VERSION 5.8 ;
BUSBITCHARS "[]" ;
DIVIDERCHAR "/" ;
UNITS
    DATABASE MICRONS 1000 ;
END UNITS

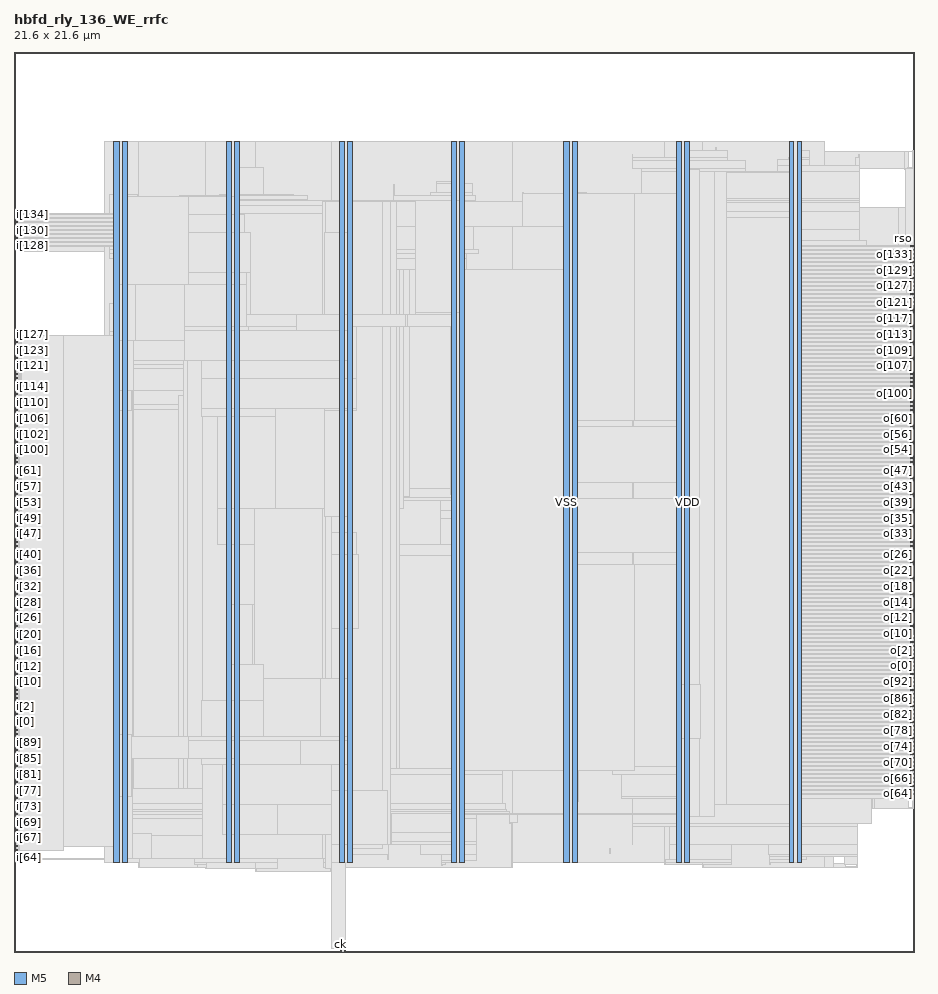
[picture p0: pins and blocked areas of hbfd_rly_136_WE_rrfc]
MACRO hbfd_rly_136_WE_rrfc
  FOREIGN hbfd_rly_136_WE_rrfc 0 0 ;
  CLASS BLOCK ;
  SIZE 21.6 BY 21.6 ;
  PIN ck
    DIRECTION INPUT ;
    USE SIGNAL ;
    PORT
      LAYER M5 ;
        RECT  7.824 0 7.848 0.084 ;
    END
  END ck
  PIN i[0]
    DIRECTION INPUT ;
    USE SIGNAL ;
    PORT
      LAYER M4 ;
        RECT  0 5.52 0.084 5.544 ;
    END
  END i[0]
  PIN i[100]
    DIRECTION INPUT ;
    USE SIGNAL ;
    PORT
      LAYER M4 ;
        RECT  0 12.048 0.084 12.072 ;
    END
  END i[100]
  PIN i[101]
    DIRECTION INPUT ;
    USE SIGNAL ;
    PORT
      LAYER M4 ;
        RECT  0 12.144 0.084 12.168 ;
    END
  END i[101]
  PIN i[102]
    DIRECTION INPUT ;
    USE SIGNAL ;
    PORT
      LAYER M4 ;
        RECT  0 12.24 0.084 12.264 ;
    END
  END i[102]
  PIN i[103]
    DIRECTION INPUT ;
    USE SIGNAL ;
    PORT
      LAYER M4 ;
        RECT  0 12.336 0.084 12.36 ;
    END
  END i[103]
  PIN i[104]
    DIRECTION INPUT ;
    USE SIGNAL ;
    PORT
      LAYER M4 ;
        RECT  0 12.432 0.084 12.456 ;
    END
  END i[104]
  PIN i[105]
    DIRECTION INPUT ;
    USE SIGNAL ;
    PORT
      LAYER M4 ;
        RECT  0 12.528 0.084 12.552 ;
    END
  END i[105]
  PIN i[106]
    DIRECTION INPUT ;
    USE SIGNAL ;
    PORT
      LAYER M4 ;
        RECT  0 12.624 0.084 12.648 ;
    END
  END i[106]
  PIN i[107]
    DIRECTION INPUT ;
    USE SIGNAL ;
    PORT
      LAYER M4 ;
        RECT  0 12.72 0.084 12.744 ;
    END
  END i[107]
  PIN i[108]
    DIRECTION INPUT ;
    USE SIGNAL ;
    PORT
      LAYER M4 ;
        RECT  0 12.816 0.084 12.84 ;
    END
  END i[108]
  PIN i[109]
    DIRECTION INPUT ;
    USE SIGNAL ;
    PORT
      LAYER M4 ;
        RECT  0 12.912 0.084 12.936 ;
    END
  END i[109]
  PIN i[10]
    DIRECTION INPUT ;
    USE SIGNAL ;
    PORT
      LAYER M4 ;
        RECT  0 6.48 0.084 6.504 ;
    END
  END i[10]
  PIN i[110]
    DIRECTION INPUT ;
    USE SIGNAL ;
    PORT
      LAYER M4 ;
        RECT  0 13.008 0.084 13.032 ;
    END
  END i[110]
  PIN i[111]
    DIRECTION INPUT ;
    USE SIGNAL ;
    PORT
      LAYER M4 ;
        RECT  0 13.104 0.084 13.128 ;
    END
  END i[111]
  PIN i[112]
    DIRECTION INPUT ;
    USE SIGNAL ;
    PORT
      LAYER M4 ;
        RECT  0 13.2 0.084 13.224 ;
    END
  END i[112]
  PIN i[113]
    DIRECTION INPUT ;
    USE SIGNAL ;
    PORT
      LAYER M4 ;
        RECT  0 13.296 0.084 13.32 ;
    END
  END i[113]
  PIN i[114]
    DIRECTION INPUT ;
    USE SIGNAL ;
    PORT
      LAYER M4 ;
        RECT  0 13.392 0.084 13.416 ;
    END
  END i[114]
  PIN i[115]
    DIRECTION INPUT ;
    USE SIGNAL ;
    PORT
      LAYER M4 ;
        RECT  0 13.488 0.084 13.512 ;
    END
  END i[115]
  PIN i[116]
    DIRECTION INPUT ;
    USE SIGNAL ;
    PORT
      LAYER M4 ;
        RECT  0 13.584 0.084 13.608 ;
    END
  END i[116]
  PIN i[117]
    DIRECTION INPUT ;
    USE SIGNAL ;
    PORT
      LAYER M4 ;
        RECT  0 13.68 0.084 13.704 ;
    END
  END i[117]
  PIN i[118]
    DIRECTION INPUT ;
    USE SIGNAL ;
    PORT
      LAYER M4 ;
        RECT  0 13.776 0.084 13.8 ;
    END
  END i[118]
  PIN i[119]
    DIRECTION INPUT ;
    USE SIGNAL ;
    PORT
      LAYER M4 ;
        RECT  0 13.872 0.084 13.896 ;
    END
  END i[119]
  PIN i[11]
    DIRECTION INPUT ;
    USE SIGNAL ;
    PORT
      LAYER M4 ;
        RECT  0 6.576 0.084 6.6 ;
    END
  END i[11]
  PIN i[120]
    DIRECTION INPUT ;
    USE SIGNAL ;
    PORT
      LAYER M4 ;
        RECT  0 13.968 0.084 13.992 ;
    END
  END i[120]
  PIN i[121]
    DIRECTION INPUT ;
    USE SIGNAL ;
    PORT
      LAYER M4 ;
        RECT  0 14.064 0.084 14.088 ;
    END
  END i[121]
  PIN i[122]
    DIRECTION INPUT ;
    USE SIGNAL ;
    PORT
      LAYER M4 ;
        RECT  0 14.16 0.084 14.184 ;
    END
  END i[122]
  PIN i[123]
    DIRECTION INPUT ;
    USE SIGNAL ;
    PORT
      LAYER M4 ;
        RECT  0 14.256 0.084 14.28 ;
    END
  END i[123]
  PIN i[124]
    DIRECTION INPUT ;
    USE SIGNAL ;
    PORT
      LAYER M4 ;
        RECT  0 14.352 0.084 14.376 ;
    END
  END i[124]
  PIN i[125]
    DIRECTION INPUT ;
    USE SIGNAL ;
    PORT
      LAYER M4 ;
        RECT  0 14.448 0.084 14.472 ;
    END
  END i[125]
  PIN i[126]
    DIRECTION INPUT ;
    USE SIGNAL ;
    PORT
      LAYER M4 ;
        RECT  0 14.544 0.084 14.568 ;
    END
  END i[126]
  PIN i[127]
    DIRECTION INPUT ;
    USE SIGNAL ;
    PORT
      LAYER M4 ;
        RECT  0 14.64 0.084 14.664 ;
    END
  END i[127]
  PIN i[128]
    DIRECTION INPUT ;
    USE SIGNAL ;
    PORT
      LAYER M4 ;
        RECT  0 16.944 0.084 16.968 ;
    END
  END i[128]
  PIN i[129]
    DIRECTION INPUT ;
    USE SIGNAL ;
    PORT
      LAYER M4 ;
        RECT  0 17.04 0.084 17.064 ;
    END
  END i[129]
  PIN i[12]
    DIRECTION INPUT ;
    USE SIGNAL ;
    PORT
      LAYER M4 ;
        RECT  0 6.672 0.084 6.696 ;
    END
  END i[12]
  PIN i[130]
    DIRECTION INPUT ;
    USE SIGNAL ;
    PORT
      LAYER M4 ;
        RECT  0 17.136 0.084 17.16 ;
    END
  END i[130]
  PIN i[131]
    DIRECTION INPUT ;
    USE SIGNAL ;
    PORT
      LAYER M4 ;
        RECT  0 17.232 0.084 17.256 ;
    END
  END i[131]
  PIN i[132]
    DIRECTION INPUT ;
    USE SIGNAL ;
    PORT
      LAYER M4 ;
        RECT  0 17.328 0.084 17.352 ;
    END
  END i[132]
  PIN i[133]
    DIRECTION INPUT ;
    USE SIGNAL ;
    PORT
      LAYER M4 ;
        RECT  0 17.424 0.084 17.448 ;
    END
  END i[133]
  PIN i[134]
    DIRECTION INPUT ;
    USE SIGNAL ;
    PORT
      LAYER M4 ;
        RECT  0 17.52 0.084 17.544 ;
    END
  END i[134]
  PIN i[135]
    DIRECTION INPUT ;
    USE SIGNAL ;
    PORT
      LAYER M4 ;
        RECT  0 17.616 0.084 17.64 ;
    END
  END i[135]
  PIN i[13]
    DIRECTION INPUT ;
    USE SIGNAL ;
    PORT
      LAYER M4 ;
        RECT  0 6.768 0.084 6.792 ;
    END
  END i[13]
  PIN i[14]
    DIRECTION INPUT ;
    USE SIGNAL ;
    PORT
      LAYER M4 ;
        RECT  0 6.864 0.084 6.888 ;
    END
  END i[14]
  PIN i[15]
    DIRECTION INPUT ;
    USE SIGNAL ;
    PORT
      LAYER M4 ;
        RECT  0 6.96 0.084 6.984 ;
    END
  END i[15]
  PIN i[16]
    DIRECTION INPUT ;
    USE SIGNAL ;
    PORT
      LAYER M4 ;
        RECT  0 7.056 0.084 7.08 ;
    END
  END i[16]
  PIN i[17]
    DIRECTION INPUT ;
    USE SIGNAL ;
    PORT
      LAYER M4 ;
        RECT  0 7.152 0.084 7.176 ;
    END
  END i[17]
  PIN i[18]
    DIRECTION INPUT ;
    USE SIGNAL ;
    PORT
      LAYER M4 ;
        RECT  0 7.248 0.084 7.272 ;
    END
  END i[18]
  PIN i[19]
    DIRECTION INPUT ;
    USE SIGNAL ;
    PORT
      LAYER M4 ;
        RECT  0 7.344 0.084 7.368 ;
    END
  END i[19]
  PIN i[1]
    DIRECTION INPUT ;
    USE SIGNAL ;
    PORT
      LAYER M4 ;
        RECT  0 5.616 0.084 5.64 ;
    END
  END i[1]
  PIN i[20]
    DIRECTION INPUT ;
    USE SIGNAL ;
    PORT
      LAYER M4 ;
        RECT  0 7.44 0.084 7.464 ;
    END
  END i[20]
  PIN i[21]
    DIRECTION INPUT ;
    USE SIGNAL ;
    PORT
      LAYER M4 ;
        RECT  0 7.536 0.084 7.56 ;
    END
  END i[21]
  PIN i[22]
    DIRECTION INPUT ;
    USE SIGNAL ;
    PORT
      LAYER M4 ;
        RECT  0 7.632 0.084 7.656 ;
    END
  END i[22]
  PIN i[23]
    DIRECTION INPUT ;
    USE SIGNAL ;
    PORT
      LAYER M4 ;
        RECT  0 7.728 0.084 7.752 ;
    END
  END i[23]
  PIN i[24]
    DIRECTION INPUT ;
    USE SIGNAL ;
    PORT
      LAYER M4 ;
        RECT  0 7.824 0.084 7.848 ;
    END
  END i[24]
  PIN i[25]
    DIRECTION INPUT ;
    USE SIGNAL ;
    PORT
      LAYER M4 ;
        RECT  0 7.92 0.084 7.944 ;
    END
  END i[25]
  PIN i[26]
    DIRECTION INPUT ;
    USE SIGNAL ;
    PORT
      LAYER M4 ;
        RECT  0 8.016 0.084 8.04 ;
    END
  END i[26]
  PIN i[27]
    DIRECTION INPUT ;
    USE SIGNAL ;
    PORT
      LAYER M4 ;
        RECT  0 8.112 0.084 8.136 ;
    END
  END i[27]
  PIN i[28]
    DIRECTION INPUT ;
    USE SIGNAL ;
    PORT
      LAYER M4 ;
        RECT  0 8.208 0.084 8.232 ;
    END
  END i[28]
  PIN i[29]
    DIRECTION INPUT ;
    USE SIGNAL ;
    PORT
      LAYER M4 ;
        RECT  0 8.304 0.084 8.328 ;
    END
  END i[29]
  PIN i[2]
    DIRECTION INPUT ;
    USE SIGNAL ;
    PORT
      LAYER M4 ;
        RECT  0 5.712 0.084 5.736 ;
    END
  END i[2]
  PIN i[30]
    DIRECTION INPUT ;
    USE SIGNAL ;
    PORT
      LAYER M4 ;
        RECT  0 8.4 0.084 8.424 ;
    END
  END i[30]
  PIN i[31]
    DIRECTION INPUT ;
    USE SIGNAL ;
    PORT
      LAYER M4 ;
        RECT  0 8.496 0.084 8.52 ;
    END
  END i[31]
  PIN i[32]
    DIRECTION INPUT ;
    USE SIGNAL ;
    PORT
      LAYER M4 ;
        RECT  0 8.592 0.084 8.616 ;
    END
  END i[32]
  PIN i[33]
    DIRECTION INPUT ;
    USE SIGNAL ;
    PORT
      LAYER M4 ;
        RECT  0 8.688 0.084 8.712 ;
    END
  END i[33]
  PIN i[34]
    DIRECTION INPUT ;
    USE SIGNAL ;
    PORT
      LAYER M4 ;
        RECT  0 8.784 0.084 8.808 ;
    END
  END i[34]
  PIN i[35]
    DIRECTION INPUT ;
    USE SIGNAL ;
    PORT
      LAYER M4 ;
        RECT  0 8.88 0.084 8.904 ;
    END
  END i[35]
  PIN i[36]
    DIRECTION INPUT ;
    USE SIGNAL ;
    PORT
      LAYER M4 ;
        RECT  0 8.976 0.084 9 ;
    END
  END i[36]
  PIN i[37]
    DIRECTION INPUT ;
    USE SIGNAL ;
    PORT
      LAYER M4 ;
        RECT  0 9.072 0.084 9.096 ;
    END
  END i[37]
  PIN i[38]
    DIRECTION INPUT ;
    USE SIGNAL ;
    PORT
      LAYER M4 ;
        RECT  0 9.168 0.084 9.192 ;
    END
  END i[38]
  PIN i[39]
    DIRECTION INPUT ;
    USE SIGNAL ;
    PORT
      LAYER M4 ;
        RECT  0 9.264 0.084 9.288 ;
    END
  END i[39]
  PIN i[3]
    DIRECTION INPUT ;
    USE SIGNAL ;
    PORT
      LAYER M4 ;
        RECT  0 5.808 0.084 5.832 ;
    END
  END i[3]
  PIN i[40]
    DIRECTION INPUT ;
    USE SIGNAL ;
    PORT
      LAYER M4 ;
        RECT  0 9.36 0.084 9.384 ;
    END
  END i[40]
  PIN i[41]
    DIRECTION INPUT ;
    USE SIGNAL ;
    PORT
      LAYER M4 ;
        RECT  0 9.456 0.084 9.48 ;
    END
  END i[41]
  PIN i[42]
    DIRECTION INPUT ;
    USE SIGNAL ;
    PORT
      LAYER M4 ;
        RECT  0 9.552 0.084 9.576 ;
    END
  END i[42]
  PIN i[43]
    DIRECTION INPUT ;
    USE SIGNAL ;
    PORT
      LAYER M4 ;
        RECT  0 9.648 0.084 9.672 ;
    END
  END i[43]
  PIN i[44]
    DIRECTION INPUT ;
    USE SIGNAL ;
    PORT
      LAYER M4 ;
        RECT  0 9.744 0.084 9.768 ;
    END
  END i[44]
  PIN i[45]
    DIRECTION INPUT ;
    USE SIGNAL ;
    PORT
      LAYER M4 ;
        RECT  0 9.84 0.084 9.864 ;
    END
  END i[45]
  PIN i[46]
    DIRECTION INPUT ;
    USE SIGNAL ;
    PORT
      LAYER M4 ;
        RECT  0 9.936 0.084 9.96 ;
    END
  END i[46]
  PIN i[47]
    DIRECTION INPUT ;
    USE SIGNAL ;
    PORT
      LAYER M4 ;
        RECT  0 10.032 0.084 10.056 ;
    END
  END i[47]
  PIN i[48]
    DIRECTION INPUT ;
    USE SIGNAL ;
    PORT
      LAYER M4 ;
        RECT  0 10.128 0.084 10.152 ;
    END
  END i[48]
  PIN i[49]
    DIRECTION INPUT ;
    USE SIGNAL ;
    PORT
      LAYER M4 ;
        RECT  0 10.224 0.084 10.248 ;
    END
  END i[49]
  PIN i[4]
    DIRECTION INPUT ;
    USE SIGNAL ;
    PORT
      LAYER M4 ;
        RECT  0 5.904 0.084 5.928 ;
    END
  END i[4]
  PIN i[50]
    DIRECTION INPUT ;
    USE SIGNAL ;
    PORT
      LAYER M4 ;
        RECT  0 10.32 0.084 10.344 ;
    END
  END i[50]
  PIN i[51]
    DIRECTION INPUT ;
    USE SIGNAL ;
    PORT
      LAYER M4 ;
        RECT  0 10.416 0.084 10.44 ;
    END
  END i[51]
  PIN i[52]
    DIRECTION INPUT ;
    USE SIGNAL ;
    PORT
      LAYER M4 ;
        RECT  0 10.512 0.084 10.536 ;
    END
  END i[52]
  PIN i[53]
    DIRECTION INPUT ;
    USE SIGNAL ;
    PORT
      LAYER M4 ;
        RECT  0 10.608 0.084 10.632 ;
    END
  END i[53]
  PIN i[54]
    DIRECTION INPUT ;
    USE SIGNAL ;
    PORT
      LAYER M4 ;
        RECT  0 10.704 0.084 10.728 ;
    END
  END i[54]
  PIN i[55]
    DIRECTION INPUT ;
    USE SIGNAL ;
    PORT
      LAYER M4 ;
        RECT  0 10.8 0.084 10.824 ;
    END
  END i[55]
  PIN i[56]
    DIRECTION INPUT ;
    USE SIGNAL ;
    PORT
      LAYER M4 ;
        RECT  0 10.896 0.084 10.92 ;
    END
  END i[56]
  PIN i[57]
    DIRECTION INPUT ;
    USE SIGNAL ;
    PORT
      LAYER M4 ;
        RECT  0 10.992 0.084 11.016 ;
    END
  END i[57]
  PIN i[58]
    DIRECTION INPUT ;
    USE SIGNAL ;
    PORT
      LAYER M4 ;
        RECT  0 11.088 0.084 11.112 ;
    END
  END i[58]
  PIN i[59]
    DIRECTION INPUT ;
    USE SIGNAL ;
    PORT
      LAYER M4 ;
        RECT  0 11.184 0.084 11.208 ;
    END
  END i[59]
  PIN i[5]
    DIRECTION INPUT ;
    USE SIGNAL ;
    PORT
      LAYER M4 ;
        RECT  0 6 0.084 6.024 ;
    END
  END i[5]
  PIN i[60]
    DIRECTION INPUT ;
    USE SIGNAL ;
    PORT
      LAYER M4 ;
        RECT  0 11.28 0.084 11.304 ;
    END
  END i[60]
  PIN i[61]
    DIRECTION INPUT ;
    USE SIGNAL ;
    PORT
      LAYER M4 ;
        RECT  0 11.376 0.084 11.4 ;
    END
  END i[61]
  PIN i[62]
    DIRECTION INPUT ;
    USE SIGNAL ;
    PORT
      LAYER M4 ;
        RECT  0 11.472 0.084 11.496 ;
    END
  END i[62]
  PIN i[63]
    DIRECTION INPUT ;
    USE SIGNAL ;
    PORT
      LAYER M4 ;
        RECT  0 11.568 0.084 11.592 ;
    END
  END i[63]
  PIN i[64]
    DIRECTION INPUT ;
    USE SIGNAL ;
    PORT
      LAYER M4 ;
        RECT  0 2.448 0.084 2.472 ;
    END
  END i[64]
  PIN i[65]
    DIRECTION INPUT ;
    USE SIGNAL ;
    PORT
      LAYER M4 ;
        RECT  0 2.544 0.084 2.568 ;
    END
  END i[65]
  PIN i[66]
    DIRECTION INPUT ;
    USE SIGNAL ;
    PORT
      LAYER M4 ;
        RECT  0 2.64 0.084 2.664 ;
    END
  END i[66]
  PIN i[67]
    DIRECTION INPUT ;
    USE SIGNAL ;
    PORT
      LAYER M4 ;
        RECT  0 2.736 0.084 2.76 ;
    END
  END i[67]
  PIN i[68]
    DIRECTION INPUT ;
    USE SIGNAL ;
    PORT
      LAYER M4 ;
        RECT  0 2.832 0.084 2.856 ;
    END
  END i[68]
  PIN i[69]
    DIRECTION INPUT ;
    USE SIGNAL ;
    PORT
      LAYER M4 ;
        RECT  0 2.928 0.084 2.952 ;
    END
  END i[69]
  PIN i[6]
    DIRECTION INPUT ;
    USE SIGNAL ;
    PORT
      LAYER M4 ;
        RECT  0 6.096 0.084 6.12 ;
    END
  END i[6]
  PIN i[70]
    DIRECTION INPUT ;
    USE SIGNAL ;
    PORT
      LAYER M4 ;
        RECT  0 3.024 0.084 3.048 ;
    END
  END i[70]
  PIN i[71]
    DIRECTION INPUT ;
    USE SIGNAL ;
    PORT
      LAYER M4 ;
        RECT  0 3.12 0.084 3.144 ;
    END
  END i[71]
  PIN i[72]
    DIRECTION INPUT ;
    USE SIGNAL ;
    PORT
      LAYER M4 ;
        RECT  0 3.216 0.084 3.24 ;
    END
  END i[72]
  PIN i[73]
    DIRECTION INPUT ;
    USE SIGNAL ;
    PORT
      LAYER M4 ;
        RECT  0 3.312 0.084 3.336 ;
    END
  END i[73]
  PIN i[74]
    DIRECTION INPUT ;
    USE SIGNAL ;
    PORT
      LAYER M4 ;
        RECT  0 3.408 0.084 3.432 ;
    END
  END i[74]
  PIN i[75]
    DIRECTION INPUT ;
    USE SIGNAL ;
    PORT
      LAYER M4 ;
        RECT  0 3.504 0.084 3.528 ;
    END
  END i[75]
  PIN i[76]
    DIRECTION INPUT ;
    USE SIGNAL ;
    PORT
      LAYER M4 ;
        RECT  0 3.6 0.084 3.624 ;
    END
  END i[76]
  PIN i[77]
    DIRECTION INPUT ;
    USE SIGNAL ;
    PORT
      LAYER M4 ;
        RECT  0 3.696 0.084 3.72 ;
    END
  END i[77]
  PIN i[78]
    DIRECTION INPUT ;
    USE SIGNAL ;
    PORT
      LAYER M4 ;
        RECT  0 3.792 0.084 3.816 ;
    END
  END i[78]
  PIN i[79]
    DIRECTION INPUT ;
    USE SIGNAL ;
    PORT
      LAYER M4 ;
        RECT  0 3.888 0.084 3.912 ;
    END
  END i[79]
  PIN i[7]
    DIRECTION INPUT ;
    USE SIGNAL ;
    PORT
      LAYER M4 ;
        RECT  0 6.192 0.084 6.216 ;
    END
  END i[7]
  PIN i[80]
    DIRECTION INPUT ;
    USE SIGNAL ;
    PORT
      LAYER M4 ;
        RECT  0 3.984 0.084 4.008 ;
    END
  END i[80]
  PIN i[81]
    DIRECTION INPUT ;
    USE SIGNAL ;
    PORT
      LAYER M4 ;
        RECT  0 4.08 0.084 4.104 ;
    END
  END i[81]
  PIN i[82]
    DIRECTION INPUT ;
    USE SIGNAL ;
    PORT
      LAYER M4 ;
        RECT  0 4.176 0.084 4.2 ;
    END
  END i[82]
  PIN i[83]
    DIRECTION INPUT ;
    USE SIGNAL ;
    PORT
      LAYER M4 ;
        RECT  0 4.272 0.084 4.296 ;
    END
  END i[83]
  PIN i[84]
    DIRECTION INPUT ;
    USE SIGNAL ;
    PORT
      LAYER M4 ;
        RECT  0 4.368 0.084 4.392 ;
    END
  END i[84]
  PIN i[85]
    DIRECTION INPUT ;
    USE SIGNAL ;
    PORT
      LAYER M4 ;
        RECT  0 4.464 0.084 4.488 ;
    END
  END i[85]
  PIN i[86]
    DIRECTION INPUT ;
    USE SIGNAL ;
    PORT
      LAYER M4 ;
        RECT  0 4.56 0.084 4.584 ;
    END
  END i[86]
  PIN i[87]
    DIRECTION INPUT ;
    USE SIGNAL ;
    PORT
      LAYER M4 ;
        RECT  0 4.656 0.084 4.68 ;
    END
  END i[87]
  PIN i[88]
    DIRECTION INPUT ;
    USE SIGNAL ;
    PORT
      LAYER M4 ;
        RECT  0 4.752 0.084 4.776 ;
    END
  END i[88]
  PIN i[89]
    DIRECTION INPUT ;
    USE SIGNAL ;
    PORT
      LAYER M4 ;
        RECT  0 4.848 0.084 4.872 ;
    END
  END i[89]
  PIN i[8]
    DIRECTION INPUT ;
    USE SIGNAL ;
    PORT
      LAYER M4 ;
        RECT  0 6.288 0.084 6.312 ;
    END
  END i[8]
  PIN i[90]
    DIRECTION INPUT ;
    USE SIGNAL ;
    PORT
      LAYER M4 ;
        RECT  0 4.944 0.084 4.968 ;
    END
  END i[90]
  PIN i[91]
    DIRECTION INPUT ;
    USE SIGNAL ;
    PORT
      LAYER M4 ;
        RECT  0 5.04 0.084 5.064 ;
    END
  END i[91]
  PIN i[92]
    DIRECTION INPUT ;
    USE SIGNAL ;
    PORT
      LAYER M4 ;
        RECT  0 5.136 0.084 5.16 ;
    END
  END i[92]
  PIN i[93]
    DIRECTION INPUT ;
    USE SIGNAL ;
    PORT
      LAYER M4 ;
        RECT  0 5.232 0.084 5.256 ;
    END
  END i[93]
  PIN i[94]
    DIRECTION INPUT ;
    USE SIGNAL ;
    PORT
      LAYER M4 ;
        RECT  0 5.328 0.084 5.352 ;
    END
  END i[94]
  PIN i[95]
    DIRECTION INPUT ;
    USE SIGNAL ;
    PORT
      LAYER M4 ;
        RECT  0 5.424 0.084 5.448 ;
    END
  END i[95]
  PIN i[96]
    DIRECTION INPUT ;
    USE SIGNAL ;
    PORT
      LAYER M4 ;
        RECT  0 11.664 0.084 11.688 ;
    END
  END i[96]
  PIN i[97]
    DIRECTION INPUT ;
    USE SIGNAL ;
    PORT
      LAYER M4 ;
        RECT  0 11.76 0.084 11.784 ;
    END
  END i[97]
  PIN i[98]
    DIRECTION INPUT ;
    USE SIGNAL ;
    PORT
      LAYER M4 ;
        RECT  0 11.856 0.084 11.88 ;
    END
  END i[98]
  PIN i[99]
    DIRECTION INPUT ;
    USE SIGNAL ;
    PORT
      LAYER M4 ;
        RECT  0 11.952 0.084 11.976 ;
    END
  END i[99]
  PIN i[9]
    DIRECTION INPUT ;
    USE SIGNAL ;
    PORT
      LAYER M4 ;
        RECT  0 6.384 0.084 6.408 ;
    END
  END i[9]
  PIN o[0]
    DIRECTION OUTPUT ;
    USE SIGNAL ;
    PORT
      LAYER M4 ;
        RECT  21.516 6.864 21.6 6.888 ;
    END
  END o[0]
  PIN o[100]
    DIRECTION OUTPUT ;
    USE SIGNAL ;
    PORT
      LAYER M4 ;
        RECT  21.516 13.392 21.6 13.416 ;
    END
  END o[100]
  PIN o[101]
    DIRECTION OUTPUT ;
    USE SIGNAL ;
    PORT
      LAYER M4 ;
        RECT  21.516 13.488 21.6 13.512 ;
    END
  END o[101]
  PIN o[102]
    DIRECTION OUTPUT ;
    USE SIGNAL ;
    PORT
      LAYER M4 ;
        RECT  21.516 13.584 21.6 13.608 ;
    END
  END o[102]
  PIN o[103]
    DIRECTION OUTPUT ;
    USE SIGNAL ;
    PORT
      LAYER M4 ;
        RECT  21.516 13.68 21.6 13.704 ;
    END
  END o[103]
  PIN o[104]
    DIRECTION OUTPUT ;
    USE SIGNAL ;
    PORT
      LAYER M4 ;
        RECT  21.516 13.776 21.6 13.8 ;
    END
  END o[104]
  PIN o[105]
    DIRECTION OUTPUT ;
    USE SIGNAL ;
    PORT
      LAYER M4 ;
        RECT  21.516 13.872 21.6 13.896 ;
    END
  END o[105]
  PIN o[106]
    DIRECTION OUTPUT ;
    USE SIGNAL ;
    PORT
      LAYER M4 ;
        RECT  21.516 13.968 21.6 13.992 ;
    END
  END o[106]
  PIN o[107]
    DIRECTION OUTPUT ;
    USE SIGNAL ;
    PORT
      LAYER M4 ;
        RECT  21.516 14.064 21.6 14.088 ;
    END
  END o[107]
  PIN o[108]
    DIRECTION OUTPUT ;
    USE SIGNAL ;
    PORT
      LAYER M4 ;
        RECT  21.516 14.16 21.6 14.184 ;
    END
  END o[108]
  PIN o[109]
    DIRECTION OUTPUT ;
    USE SIGNAL ;
    PORT
      LAYER M4 ;
        RECT  21.516 14.256 21.6 14.28 ;
    END
  END o[109]
  PIN o[10]
    DIRECTION OUTPUT ;
    USE SIGNAL ;
    PORT
      LAYER M4 ;
        RECT  21.516 7.824 21.6 7.848 ;
    END
  END o[10]
  PIN o[110]
    DIRECTION OUTPUT ;
    USE SIGNAL ;
    PORT
      LAYER M4 ;
        RECT  21.516 14.352 21.6 14.376 ;
    END
  END o[110]
  PIN o[111]
    DIRECTION OUTPUT ;
    USE SIGNAL ;
    PORT
      LAYER M4 ;
        RECT  21.516 14.448 21.6 14.472 ;
    END
  END o[111]
  PIN o[112]
    DIRECTION OUTPUT ;
    USE SIGNAL ;
    PORT
      LAYER M4 ;
        RECT  21.516 14.544 21.6 14.568 ;
    END
  END o[112]
  PIN o[113]
    DIRECTION OUTPUT ;
    USE SIGNAL ;
    PORT
      LAYER M4 ;
        RECT  21.516 14.64 21.6 14.664 ;
    END
  END o[113]
  PIN o[114]
    DIRECTION OUTPUT ;
    USE SIGNAL ;
    PORT
      LAYER M4 ;
        RECT  21.516 14.736 21.6 14.76 ;
    END
  END o[114]
  PIN o[115]
    DIRECTION OUTPUT ;
    USE SIGNAL ;
    PORT
      LAYER M4 ;
        RECT  21.516 14.832 21.6 14.856 ;
    END
  END o[115]
  PIN o[116]
    DIRECTION OUTPUT ;
    USE SIGNAL ;
    PORT
      LAYER M4 ;
        RECT  21.516 14.928 21.6 14.952 ;
    END
  END o[116]
  PIN o[117]
    DIRECTION OUTPUT ;
    USE SIGNAL ;
    PORT
      LAYER M4 ;
        RECT  21.516 15.024 21.6 15.048 ;
    END
  END o[117]
  PIN o[118]
    DIRECTION OUTPUT ;
    USE SIGNAL ;
    PORT
      LAYER M4 ;
        RECT  21.516 15.12 21.6 15.144 ;
    END
  END o[118]
  PIN o[119]
    DIRECTION OUTPUT ;
    USE SIGNAL ;
    PORT
      LAYER M4 ;
        RECT  21.516 15.216 21.6 15.24 ;
    END
  END o[119]
  PIN o[11]
    DIRECTION OUTPUT ;
    USE SIGNAL ;
    PORT
      LAYER M4 ;
        RECT  21.516 7.92 21.6 7.944 ;
    END
  END o[11]
  PIN o[120]
    DIRECTION OUTPUT ;
    USE SIGNAL ;
    PORT
      LAYER M4 ;
        RECT  21.516 15.312 21.6 15.336 ;
    END
  END o[120]
  PIN o[121]
    DIRECTION OUTPUT ;
    USE SIGNAL ;
    PORT
      LAYER M4 ;
        RECT  21.516 15.408 21.6 15.432 ;
    END
  END o[121]
  PIN o[122]
    DIRECTION OUTPUT ;
    USE SIGNAL ;
    PORT
      LAYER M4 ;
        RECT  21.516 15.504 21.6 15.528 ;
    END
  END o[122]
  PIN o[123]
    DIRECTION OUTPUT ;
    USE SIGNAL ;
    PORT
      LAYER M4 ;
        RECT  21.516 15.6 21.6 15.624 ;
    END
  END o[123]
  PIN o[124]
    DIRECTION OUTPUT ;
    USE SIGNAL ;
    PORT
      LAYER M4 ;
        RECT  21.516 15.696 21.6 15.72 ;
    END
  END o[124]
  PIN o[125]
    DIRECTION OUTPUT ;
    USE SIGNAL ;
    PORT
      LAYER M4 ;
        RECT  21.516 15.792 21.6 15.816 ;
    END
  END o[125]
  PIN o[126]
    DIRECTION OUTPUT ;
    USE SIGNAL ;
    PORT
      LAYER M4 ;
        RECT  21.516 15.888 21.6 15.912 ;
    END
  END o[126]
  PIN o[127]
    DIRECTION OUTPUT ;
    USE SIGNAL ;
    PORT
      LAYER M4 ;
        RECT  21.516 15.984 21.6 16.008 ;
    END
  END o[127]
  PIN o[128]
    DIRECTION OUTPUT ;
    USE SIGNAL ;
    PORT
      LAYER M4 ;
        RECT  21.516 16.08 21.6 16.104 ;
    END
  END o[128]
  PIN o[129]
    DIRECTION OUTPUT ;
    USE SIGNAL ;
    PORT
      LAYER M4 ;
        RECT  21.516 16.176 21.6 16.2 ;
    END
  END o[129]
  PIN o[12]
    DIRECTION OUTPUT ;
    USE SIGNAL ;
    PORT
      LAYER M4 ;
        RECT  21.516 8.016 21.6 8.04 ;
    END
  END o[12]
  PIN o[130]
    DIRECTION OUTPUT ;
    USE SIGNAL ;
    PORT
      LAYER M4 ;
        RECT  21.516 16.272 21.6 16.296 ;
    END
  END o[130]
  PIN o[131]
    DIRECTION OUTPUT ;
    USE SIGNAL ;
    PORT
      LAYER M4 ;
        RECT  21.516 16.368 21.6 16.392 ;
    END
  END o[131]
  PIN o[132]
    DIRECTION OUTPUT ;
    USE SIGNAL ;
    PORT
      LAYER M4 ;
        RECT  21.516 16.464 21.6 16.488 ;
    END
  END o[132]
  PIN o[133]
    DIRECTION OUTPUT ;
    USE SIGNAL ;
    PORT
      LAYER M4 ;
        RECT  21.516 16.56 21.6 16.584 ;
    END
  END o[133]
  PIN o[134]
    DIRECTION OUTPUT ;
    USE SIGNAL ;
    PORT
      LAYER M4 ;
        RECT  21.516 16.656 21.6 16.68 ;
    END
  END o[134]
  PIN o[135]
    DIRECTION OUTPUT ;
    USE SIGNAL ;
    PORT
      LAYER M4 ;
        RECT  21.516 16.752 21.6 16.776 ;
    END
  END o[135]
  PIN o[13]
    DIRECTION OUTPUT ;
    USE SIGNAL ;
    PORT
      LAYER M4 ;
        RECT  21.516 8.112 21.6 8.136 ;
    END
  END o[13]
  PIN o[14]
    DIRECTION OUTPUT ;
    USE SIGNAL ;
    PORT
      LAYER M4 ;
        RECT  21.516 8.208 21.6 8.232 ;
    END
  END o[14]
  PIN o[15]
    DIRECTION OUTPUT ;
    USE SIGNAL ;
    PORT
      LAYER M4 ;
        RECT  21.516 8.304 21.6 8.328 ;
    END
  END o[15]
  PIN o[16]
    DIRECTION OUTPUT ;
    USE SIGNAL ;
    PORT
      LAYER M4 ;
        RECT  21.516 8.4 21.6 8.424 ;
    END
  END o[16]
  PIN o[17]
    DIRECTION OUTPUT ;
    USE SIGNAL ;
    PORT
      LAYER M4 ;
        RECT  21.516 8.496 21.6 8.52 ;
    END
  END o[17]
  PIN o[18]
    DIRECTION OUTPUT ;
    USE SIGNAL ;
    PORT
      LAYER M4 ;
        RECT  21.516 8.592 21.6 8.616 ;
    END
  END o[18]
  PIN o[19]
    DIRECTION OUTPUT ;
    USE SIGNAL ;
    PORT
      LAYER M4 ;
        RECT  21.516 8.688 21.6 8.712 ;
    END
  END o[19]
  PIN o[1]
    DIRECTION OUTPUT ;
    USE SIGNAL ;
    PORT
      LAYER M4 ;
        RECT  21.516 6.96 21.6 6.984 ;
    END
  END o[1]
  PIN o[20]
    DIRECTION OUTPUT ;
    USE SIGNAL ;
    PORT
      LAYER M4 ;
        RECT  21.516 8.784 21.6 8.808 ;
    END
  END o[20]
  PIN o[21]
    DIRECTION OUTPUT ;
    USE SIGNAL ;
    PORT
      LAYER M4 ;
        RECT  21.516 8.88 21.6 8.904 ;
    END
  END o[21]
  PIN o[22]
    DIRECTION OUTPUT ;
    USE SIGNAL ;
    PORT
      LAYER M4 ;
        RECT  21.516 8.976 21.6 9 ;
    END
  END o[22]
  PIN o[23]
    DIRECTION OUTPUT ;
    USE SIGNAL ;
    PORT
      LAYER M4 ;
        RECT  21.516 9.072 21.6 9.096 ;
    END
  END o[23]
  PIN o[24]
    DIRECTION OUTPUT ;
    USE SIGNAL ;
    PORT
      LAYER M4 ;
        RECT  21.516 9.168 21.6 9.192 ;
    END
  END o[24]
  PIN o[25]
    DIRECTION OUTPUT ;
    USE SIGNAL ;
    PORT
      LAYER M4 ;
        RECT  21.516 9.264 21.6 9.288 ;
    END
  END o[25]
  PIN o[26]
    DIRECTION OUTPUT ;
    USE SIGNAL ;
    PORT
      LAYER M4 ;
        RECT  21.516 9.36 21.6 9.384 ;
    END
  END o[26]
  PIN o[27]
    DIRECTION OUTPUT ;
    USE SIGNAL ;
    PORT
      LAYER M4 ;
        RECT  21.516 9.456 21.6 9.48 ;
    END
  END o[27]
  PIN o[28]
    DIRECTION OUTPUT ;
    USE SIGNAL ;
    PORT
      LAYER M4 ;
        RECT  21.516 9.552 21.6 9.576 ;
    END
  END o[28]
  PIN o[29]
    DIRECTION OUTPUT ;
    USE SIGNAL ;
    PORT
      LAYER M4 ;
        RECT  21.516 9.648 21.6 9.672 ;
    END
  END o[29]
  PIN o[2]
    DIRECTION OUTPUT ;
    USE SIGNAL ;
    PORT
      LAYER M4 ;
        RECT  21.516 7.056 21.6 7.08 ;
    END
  END o[2]
  PIN o[30]
    DIRECTION OUTPUT ;
    USE SIGNAL ;
    PORT
      LAYER M4 ;
        RECT  21.516 9.744 21.6 9.768 ;
    END
  END o[30]
  PIN o[31]
    DIRECTION OUTPUT ;
    USE SIGNAL ;
    PORT
      LAYER M4 ;
        RECT  21.516 9.84 21.6 9.864 ;
    END
  END o[31]
  PIN o[32]
    DIRECTION OUTPUT ;
    USE SIGNAL ;
    PORT
      LAYER M4 ;
        RECT  21.516 9.936 21.6 9.96 ;
    END
  END o[32]
  PIN o[33]
    DIRECTION OUTPUT ;
    USE SIGNAL ;
    PORT
      LAYER M4 ;
        RECT  21.516 10.032 21.6 10.056 ;
    END
  END o[33]
  PIN o[34]
    DIRECTION OUTPUT ;
    USE SIGNAL ;
    PORT
      LAYER M4 ;
        RECT  21.516 10.128 21.6 10.152 ;
    END
  END o[34]
  PIN o[35]
    DIRECTION OUTPUT ;
    USE SIGNAL ;
    PORT
      LAYER M4 ;
        RECT  21.516 10.224 21.6 10.248 ;
    END
  END o[35]
  PIN o[36]
    DIRECTION OUTPUT ;
    USE SIGNAL ;
    PORT
      LAYER M4 ;
        RECT  21.516 10.32 21.6 10.344 ;
    END
  END o[36]
  PIN o[37]
    DIRECTION OUTPUT ;
    USE SIGNAL ;
    PORT
      LAYER M4 ;
        RECT  21.516 10.416 21.6 10.44 ;
    END
  END o[37]
  PIN o[38]
    DIRECTION OUTPUT ;
    USE SIGNAL ;
    PORT
      LAYER M4 ;
        RECT  21.516 10.512 21.6 10.536 ;
    END
  END o[38]
  PIN o[39]
    DIRECTION OUTPUT ;
    USE SIGNAL ;
    PORT
      LAYER M4 ;
        RECT  21.516 10.608 21.6 10.632 ;
    END
  END o[39]
  PIN o[3]
    DIRECTION OUTPUT ;
    USE SIGNAL ;
    PORT
      LAYER M4 ;
        RECT  21.516 7.152 21.6 7.176 ;
    END
  END o[3]
  PIN o[40]
    DIRECTION OUTPUT ;
    USE SIGNAL ;
    PORT
      LAYER M4 ;
        RECT  21.516 10.704 21.6 10.728 ;
    END
  END o[40]
  PIN o[41]
    DIRECTION OUTPUT ;
    USE SIGNAL ;
    PORT
      LAYER M4 ;
        RECT  21.516 10.8 21.6 10.824 ;
    END
  END o[41]
  PIN o[42]
    DIRECTION OUTPUT ;
    USE SIGNAL ;
    PORT
      LAYER M4 ;
        RECT  21.516 10.896 21.6 10.92 ;
    END
  END o[42]
  PIN o[43]
    DIRECTION OUTPUT ;
    USE SIGNAL ;
    PORT
      LAYER M4 ;
        RECT  21.516 10.992 21.6 11.016 ;
    END
  END o[43]
  PIN o[44]
    DIRECTION OUTPUT ;
    USE SIGNAL ;
    PORT
      LAYER M4 ;
        RECT  21.516 11.088 21.6 11.112 ;
    END
  END o[44]
  PIN o[45]
    DIRECTION OUTPUT ;
    USE SIGNAL ;
    PORT
      LAYER M4 ;
        RECT  21.516 11.184 21.6 11.208 ;
    END
  END o[45]
  PIN o[46]
    DIRECTION OUTPUT ;
    USE SIGNAL ;
    PORT
      LAYER M4 ;
        RECT  21.516 11.28 21.6 11.304 ;
    END
  END o[46]
  PIN o[47]
    DIRECTION OUTPUT ;
    USE SIGNAL ;
    PORT
      LAYER M4 ;
        RECT  21.516 11.376 21.6 11.4 ;
    END
  END o[47]
  PIN o[48]
    DIRECTION OUTPUT ;
    USE SIGNAL ;
    PORT
      LAYER M4 ;
        RECT  21.516 11.472 21.6 11.496 ;
    END
  END o[48]
  PIN o[49]
    DIRECTION OUTPUT ;
    USE SIGNAL ;
    PORT
      LAYER M4 ;
        RECT  21.516 11.568 21.6 11.592 ;
    END
  END o[49]
  PIN o[4]
    DIRECTION OUTPUT ;
    USE SIGNAL ;
    PORT
      LAYER M4 ;
        RECT  21.516 7.248 21.6 7.272 ;
    END
  END o[4]
  PIN o[50]
    DIRECTION OUTPUT ;
    USE SIGNAL ;
    PORT
      LAYER M4 ;
        RECT  21.516 11.664 21.6 11.688 ;
    END
  END o[50]
  PIN o[51]
    DIRECTION OUTPUT ;
    USE SIGNAL ;
    PORT
      LAYER M4 ;
        RECT  21.516 11.76 21.6 11.784 ;
    END
  END o[51]
  PIN o[52]
    DIRECTION OUTPUT ;
    USE SIGNAL ;
    PORT
      LAYER M4 ;
        RECT  21.516 11.856 21.6 11.88 ;
    END
  END o[52]
  PIN o[53]
    DIRECTION OUTPUT ;
    USE SIGNAL ;
    PORT
      LAYER M4 ;
        RECT  21.516 11.952 21.6 11.976 ;
    END
  END o[53]
  PIN o[54]
    DIRECTION OUTPUT ;
    USE SIGNAL ;
    PORT
      LAYER M4 ;
        RECT  21.516 12.048 21.6 12.072 ;
    END
  END o[54]
  PIN o[55]
    DIRECTION OUTPUT ;
    USE SIGNAL ;
    PORT
      LAYER M4 ;
        RECT  21.516 12.144 21.6 12.168 ;
    END
  END o[55]
  PIN o[56]
    DIRECTION OUTPUT ;
    USE SIGNAL ;
    PORT
      LAYER M4 ;
        RECT  21.516 12.24 21.6 12.264 ;
    END
  END o[56]
  PIN o[57]
    DIRECTION OUTPUT ;
    USE SIGNAL ;
    PORT
      LAYER M4 ;
        RECT  21.516 12.336 21.6 12.36 ;
    END
  END o[57]
  PIN o[58]
    DIRECTION OUTPUT ;
    USE SIGNAL ;
    PORT
      LAYER M4 ;
        RECT  21.516 12.432 21.6 12.456 ;
    END
  END o[58]
  PIN o[59]
    DIRECTION OUTPUT ;
    USE SIGNAL ;
    PORT
      LAYER M4 ;
        RECT  21.516 12.528 21.6 12.552 ;
    END
  END o[59]
  PIN o[5]
    DIRECTION OUTPUT ;
    USE SIGNAL ;
    PORT
      LAYER M4 ;
        RECT  21.516 7.344 21.6 7.368 ;
    END
  END o[5]
  PIN o[60]
    DIRECTION OUTPUT ;
    USE SIGNAL ;
    PORT
      LAYER M4 ;
        RECT  21.516 12.624 21.6 12.648 ;
    END
  END o[60]
  PIN o[61]
    DIRECTION OUTPUT ;
    USE SIGNAL ;
    PORT
      LAYER M4 ;
        RECT  21.516 12.72 21.6 12.744 ;
    END
  END o[61]
  PIN o[62]
    DIRECTION OUTPUT ;
    USE SIGNAL ;
    PORT
      LAYER M4 ;
        RECT  21.516 12.816 21.6 12.84 ;
    END
  END o[62]
  PIN o[63]
    DIRECTION OUTPUT ;
    USE SIGNAL ;
    PORT
      LAYER M4 ;
        RECT  21.516 12.912 21.6 12.936 ;
    END
  END o[63]
  PIN o[64]
    DIRECTION OUTPUT ;
    USE SIGNAL ;
    PORT
      LAYER M4 ;
        RECT  21.516 3.792 21.6 3.816 ;
    END
  END o[64]
  PIN o[65]
    DIRECTION OUTPUT ;
    USE SIGNAL ;
    PORT
      LAYER M4 ;
        RECT  21.516 3.888 21.6 3.912 ;
    END
  END o[65]
  PIN o[66]
    DIRECTION OUTPUT ;
    USE SIGNAL ;
    PORT
      LAYER M4 ;
        RECT  21.516 3.984 21.6 4.008 ;
    END
  END o[66]
  PIN o[67]
    DIRECTION OUTPUT ;
    USE SIGNAL ;
    PORT
      LAYER M4 ;
        RECT  21.516 4.08 21.6 4.104 ;
    END
  END o[67]
  PIN o[68]
    DIRECTION OUTPUT ;
    USE SIGNAL ;
    PORT
      LAYER M4 ;
        RECT  21.516 4.176 21.6 4.2 ;
    END
  END o[68]
  PIN o[69]
    DIRECTION OUTPUT ;
    USE SIGNAL ;
    PORT
      LAYER M4 ;
        RECT  21.516 4.272 21.6 4.296 ;
    END
  END o[69]
  PIN o[6]
    DIRECTION OUTPUT ;
    USE SIGNAL ;
    PORT
      LAYER M4 ;
        RECT  21.516 7.44 21.6 7.464 ;
    END
  END o[6]
  PIN o[70]
    DIRECTION OUTPUT ;
    USE SIGNAL ;
    PORT
      LAYER M4 ;
        RECT  21.516 4.368 21.6 4.392 ;
    END
  END o[70]
  PIN o[71]
    DIRECTION OUTPUT ;
    USE SIGNAL ;
    PORT
      LAYER M4 ;
        RECT  21.516 4.464 21.6 4.488 ;
    END
  END o[71]
  PIN o[72]
    DIRECTION OUTPUT ;
    USE SIGNAL ;
    PORT
      LAYER M4 ;
        RECT  21.516 4.56 21.6 4.584 ;
    END
  END o[72]
  PIN o[73]
    DIRECTION OUTPUT ;
    USE SIGNAL ;
    PORT
      LAYER M4 ;
        RECT  21.516 4.656 21.6 4.68 ;
    END
  END o[73]
  PIN o[74]
    DIRECTION OUTPUT ;
    USE SIGNAL ;
    PORT
      LAYER M4 ;
        RECT  21.516 4.752 21.6 4.776 ;
    END
  END o[74]
  PIN o[75]
    DIRECTION OUTPUT ;
    USE SIGNAL ;
    PORT
      LAYER M4 ;
        RECT  21.516 4.848 21.6 4.872 ;
    END
  END o[75]
  PIN o[76]
    DIRECTION OUTPUT ;
    USE SIGNAL ;
    PORT
      LAYER M4 ;
        RECT  21.516 4.944 21.6 4.968 ;
    END
  END o[76]
  PIN o[77]
    DIRECTION OUTPUT ;
    USE SIGNAL ;
    PORT
      LAYER M4 ;
        RECT  21.516 5.04 21.6 5.064 ;
    END
  END o[77]
  PIN o[78]
    DIRECTION OUTPUT ;
    USE SIGNAL ;
    PORT
      LAYER M4 ;
        RECT  21.516 5.136 21.6 5.16 ;
    END
  END o[78]
  PIN o[79]
    DIRECTION OUTPUT ;
    USE SIGNAL ;
    PORT
      LAYER M4 ;
        RECT  21.516 5.232 21.6 5.256 ;
    END
  END o[79]
  PIN o[7]
    DIRECTION OUTPUT ;
    USE SIGNAL ;
    PORT
      LAYER M4 ;
        RECT  21.516 7.536 21.6 7.56 ;
    END
  END o[7]
  PIN o[80]
    DIRECTION OUTPUT ;
    USE SIGNAL ;
    PORT
      LAYER M4 ;
        RECT  21.516 5.328 21.6 5.352 ;
    END
  END o[80]
  PIN o[81]
    DIRECTION OUTPUT ;
    USE SIGNAL ;
    PORT
      LAYER M4 ;
        RECT  21.516 5.424 21.6 5.448 ;
    END
  END o[81]
  PIN o[82]
    DIRECTION OUTPUT ;
    USE SIGNAL ;
    PORT
      LAYER M4 ;
        RECT  21.516 5.52 21.6 5.544 ;
    END
  END o[82]
  PIN o[83]
    DIRECTION OUTPUT ;
    USE SIGNAL ;
    PORT
      LAYER M4 ;
        RECT  21.516 5.616 21.6 5.64 ;
    END
  END o[83]
  PIN o[84]
    DIRECTION OUTPUT ;
    USE SIGNAL ;
    PORT
      LAYER M4 ;
        RECT  21.516 5.712 21.6 5.736 ;
    END
  END o[84]
  PIN o[85]
    DIRECTION OUTPUT ;
    USE SIGNAL ;
    PORT
      LAYER M4 ;
        RECT  21.516 5.808 21.6 5.832 ;
    END
  END o[85]
  PIN o[86]
    DIRECTION OUTPUT ;
    USE SIGNAL ;
    PORT
      LAYER M4 ;
        RECT  21.516 5.904 21.6 5.928 ;
    END
  END o[86]
  PIN o[87]
    DIRECTION OUTPUT ;
    USE SIGNAL ;
    PORT
      LAYER M4 ;
        RECT  21.516 6 21.6 6.024 ;
    END
  END o[87]
  PIN o[88]
    DIRECTION OUTPUT ;
    USE SIGNAL ;
    PORT
      LAYER M4 ;
        RECT  21.516 6.096 21.6 6.12 ;
    END
  END o[88]
  PIN o[89]
    DIRECTION OUTPUT ;
    USE SIGNAL ;
    PORT
      LAYER M4 ;
        RECT  21.516 6.192 21.6 6.216 ;
    END
  END o[89]
  PIN o[8]
    DIRECTION OUTPUT ;
    USE SIGNAL ;
    PORT
      LAYER M4 ;
        RECT  21.516 7.632 21.6 7.656 ;
    END
  END o[8]
  PIN o[90]
    DIRECTION OUTPUT ;
    USE SIGNAL ;
    PORT
      LAYER M4 ;
        RECT  21.516 6.288 21.6 6.312 ;
    END
  END o[90]
  PIN o[91]
    DIRECTION OUTPUT ;
    USE SIGNAL ;
    PORT
      LAYER M4 ;
        RECT  21.516 6.384 21.6 6.408 ;
    END
  END o[91]
  PIN o[92]
    DIRECTION OUTPUT ;
    USE SIGNAL ;
    PORT
      LAYER M4 ;
        RECT  21.516 6.48 21.6 6.504 ;
    END
  END o[92]
  PIN o[93]
    DIRECTION OUTPUT ;
    USE SIGNAL ;
    PORT
      LAYER M4 ;
        RECT  21.516 6.576 21.6 6.6 ;
    END
  END o[93]
  PIN o[94]
    DIRECTION OUTPUT ;
    USE SIGNAL ;
    PORT
      LAYER M4 ;
        RECT  21.516 6.672 21.6 6.696 ;
    END
  END o[94]
  PIN o[95]
    DIRECTION OUTPUT ;
    USE SIGNAL ;
    PORT
      LAYER M4 ;
        RECT  21.516 6.768 21.6 6.792 ;
    END
  END o[95]
  PIN o[96]
    DIRECTION OUTPUT ;
    USE SIGNAL ;
    PORT
      LAYER M4 ;
        RECT  21.516 13.008 21.6 13.032 ;
    END
  END o[96]
  PIN o[97]
    DIRECTION OUTPUT ;
    USE SIGNAL ;
    PORT
      LAYER M4 ;
        RECT  21.516 13.104 21.6 13.128 ;
    END
  END o[97]
  PIN o[98]
    DIRECTION OUTPUT ;
    USE SIGNAL ;
    PORT
      LAYER M4 ;
        RECT  21.516 13.2 21.6 13.224 ;
    END
  END o[98]
  PIN o[99]
    DIRECTION OUTPUT ;
    USE SIGNAL ;
    PORT
      LAYER M4 ;
        RECT  21.516 13.296 21.6 13.32 ;
    END
  END o[99]
  PIN o[9]
    DIRECTION OUTPUT ;
    USE SIGNAL ;
    PORT
      LAYER M4 ;
        RECT  21.516 7.728 21.6 7.752 ;
    END
  END o[9]
  PIN rfi
    DIRECTION INPUT ;
    USE SIGNAL ;
    PORT
      LAYER M4 ;
        RECT  0 17.712 0.084 17.736 ;
    END
  END rfi
  PIN rfo
    DIRECTION OUTPUT ;
    USE SIGNAL ;
    PORT
      LAYER M4 ;
        RECT  21.516 16.848 21.6 16.872 ;
    END
  END rfo
  PIN rs
    DIRECTION INPUT ;
    USE SIGNAL ;
    PORT
      LAYER M5 ;
        RECT  7.92 0 7.944 0.084 ;
    END
  END rs
  PIN rso
    DIRECTION OUTPUT ;
    USE SIGNAL ;
    PORT
      LAYER M4 ;
        RECT  21.516 16.944 21.6 16.968 ;
    END
  END rso
  PIN VDD
    DIRECTION INOUT ;
    USE POWER ;
    PORT
      LAYER M5 ;
        RECT  18.792 2.151 18.912 19.449 ;
        RECT  16.092 2.151 16.212 19.449 ;
        RECT  13.392 2.151 13.512 19.449 ;
        RECT  10.692 2.151 10.812 19.449 ;
        RECT  7.992 2.151 8.112 19.449 ;
        RECT  5.292 2.151 5.412 19.449 ;
        RECT  2.592 2.151 2.712 19.449 ;
    END
  END VDD
  PIN VSS
    DIRECTION INOUT ;
    USE GROUND ;
    PORT
      LAYER M5 ;
        RECT  18.6 2.137 18.72 19.463 ;
        RECT  15.9 2.137 16.02 19.463 ;
        RECT  13.2 2.137 13.32 19.463 ;
        RECT  10.5 2.137 10.62 19.463 ;
        RECT  7.8 2.137 7.92 19.463 ;
        RECT  5.1 2.137 5.22 19.463 ;
        RECT  2.4 2.137 2.52 19.463 ;
    END
  END VSS
  # OT_OBS_CLOSED layer=M5 d_um=1.536 added=26
  OBS
    LAYER RVTN ;
     RECT  2.16 2.16 19.44 2.295 ;
     RECT  2.16 2.565 19.44 2.835 ;
     RECT  2.16 3.105 19.44 3.375 ;
     RECT  2.16 3.645 19.44 3.915 ;
     RECT  2.16 4.185 19.44 4.455 ;
     RECT  2.16 4.725 19.44 4.995 ;
     RECT  2.16 5.265 19.44 5.535 ;
     RECT  2.16 5.805 19.44 6.075 ;
     RECT  2.16 6.345 19.44 6.615 ;
     RECT  2.16 6.885 19.44 7.155 ;
     RECT  2.16 7.425 19.44 7.695 ;
     RECT  2.16 7.965 19.44 8.235 ;
     RECT  2.16 8.505 19.44 8.775 ;
     RECT  2.16 9.045 19.44 9.315 ;
     RECT  2.16 9.585 19.44 9.855 ;
     RECT  2.16 10.125 19.44 10.395 ;
     RECT  2.16 10.665 19.44 10.935 ;
     RECT  2.16 11.205 19.44 11.475 ;
     RECT  2.16 11.745 19.44 12.015 ;
     RECT  2.16 12.285 19.44 12.555 ;
     RECT  2.16 12.825 19.44 13.095 ;
     RECT  2.16 13.365 19.44 13.635 ;
     RECT  2.16 13.905 19.44 14.175 ;
     RECT  2.16 14.445 19.44 14.715 ;
     RECT  2.16 14.985 19.44 15.255 ;
     RECT  2.16 15.525 19.44 15.795 ;
     RECT  2.16 16.065 19.44 16.335 ;
     RECT  2.16 16.605 19.44 16.875 ;
     RECT  2.16 17.145 19.44 17.415 ;
     RECT  2.16 17.685 19.44 17.955 ;
     RECT  2.16 18.225 19.44 18.495 ;
     RECT  2.16 18.765 19.44 19.035 ;
     RECT  2.16 19.305 19.44 19.44 ;
    LAYER RVTP ;
     RECT  2.16 2.295 19.44 2.565 ;
     RECT  2.16 2.835 19.44 3.105 ;
     RECT  2.16 3.375 19.44 3.645 ;
     RECT  2.16 3.915 19.44 4.185 ;
     RECT  2.16 4.455 19.44 4.725 ;
     RECT  2.16 4.995 19.44 5.265 ;
     RECT  2.16 5.535 19.44 5.805 ;
     RECT  2.16 6.075 19.44 6.345 ;
     RECT  2.16 6.615 19.44 6.885 ;
     RECT  2.16 7.155 19.44 7.425 ;
     RECT  2.16 7.695 19.44 7.965 ;
     RECT  2.16 8.235 19.44 8.505 ;
     RECT  2.16 8.775 19.44 9.045 ;
     RECT  2.16 9.315 19.44 9.585 ;
     RECT  2.16 9.855 19.44 10.125 ;
     RECT  2.16 10.395 19.44 10.665 ;
     RECT  2.16 10.935 19.44 11.205 ;
     RECT  2.16 11.475 19.44 11.745 ;
     RECT  2.16 12.015 19.44 12.285 ;
     RECT  2.16 12.555 19.44 12.825 ;
     RECT  2.16 13.095 19.44 13.365 ;
     RECT  2.16 13.635 19.44 13.905 ;
     RECT  2.16 14.175 19.44 14.445 ;
     RECT  2.16 14.715 19.44 14.985 ;
     RECT  2.16 15.255 19.44 15.525 ;
     RECT  2.16 15.795 19.44 16.065 ;
     RECT  2.16 16.335 19.44 16.605 ;
     RECT  2.16 16.875 19.44 17.145 ;
     RECT  2.16 17.415 19.44 17.685 ;
     RECT  2.16 17.955 19.44 18.225 ;
     RECT  2.16 18.495 19.44 18.765 ;
     RECT  2.16 19.035 19.44 19.305 ;
    LAYER M1 ;
     RECT  2.16 2.151 19.44 19.449 ;
    LAYER M2 ;
     RECT  0.103 17.082 0.139 17.1 ;
     RECT  0.103 5.85 0.175 5.868 ;
     RECT  0.103 6.66 0.175 6.678 ;
     RECT  0.103 7.938 0.463 7.956 ;
     RECT  0.175 5.85 0.499 6.678 ;
     RECT  0.463 7.776 0.499 7.956 ;
     RECT  0.103 5.004 0.535 5.022 ;
     RECT  0.499 5.85 0.535 7.956 ;
     RECT  0.499 9.054 0.535 9.072 ;
     RECT  0.103 11.79 0.535 11.808 ;
     RECT  0.535 5.004 1.147 5.058 ;
     RECT  0.103 3.69 1.975 3.708 ;
     RECT  1.147 4.662 1.975 5.058 ;
     RECT  0.535 5.85 1.975 9.072 ;
     RECT  1.147 10.404 2.155 10.422 ;
     RECT  0.535 11.79 2.155 12.348 ;
     RECT  0.103 2.232 2.16 2.25 ;
     RECT  1.975 3.69 2.16 5.058 ;
     RECT  1.975 5.85 2.16 9.378 ;
     RECT  2.155 10.404 2.16 10.926 ;
     RECT  2.155 11.79 2.16 12.618 ;
     RECT  0.139 16.812 2.16 17.1 ;
     RECT  2.16 2.151 2.983 19.449 ;
     RECT  2.983 2.034 4.603 19.449 ;
     RECT  4.603 1.998 5.791 19.449 ;
     RECT  5.791 1.926 7.619 19.449 ;
     RECT  7.619 2.034 11.975 19.449 ;
     RECT  11.975 2.151 15.619 19.449 ;
     RECT  15.619 2.106 16.519 19.449 ;
     RECT  16.519 2.034 19.44 19.449 ;
     RECT  19.44 2.034 19.679 8.334 ;
     RECT  19.44 9.09 19.931 12.384 ;
     RECT  19.44 13.176 19.931 15.354 ;
     RECT  19.679 2.034 19.967 2.124 ;
     RECT  19.679 2.916 20.219 8.334 ;
     RECT  19.931 9.09 20.219 11.034 ;
     RECT  19.967 2.034 20.255 2.052 ;
     RECT  20.219 9.09 20.435 9.882 ;
     RECT  20.435 9.216 20.471 9.882 ;
     RECT  20.219 3.078 20.507 8.334 ;
     RECT  20.219 10.836 20.507 11.034 ;
     RECT  20.507 5.346 20.543 8.334 ;
     RECT  20.507 11.016 20.543 11.034 ;
     RECT  19.931 11.826 20.543 12.384 ;
     RECT  19.931 13.176 20.543 15.282 ;
     RECT  20.507 3.078 20.579 4.518 ;
     RECT  20.543 5.346 20.579 5.724 ;
     RECT  20.543 6.588 20.579 8.334 ;
     RECT  20.579 3.456 20.615 4.518 ;
     RECT  20.579 8.316 20.615 8.334 ;
     RECT  20.615 3.456 20.651 3.978 ;
     RECT  20.543 14.526 21.235 15.282 ;
     RECT  19.44 16.146 21.235 17.874 ;
     RECT  20.579 6.588 21.343 7.488 ;
     RECT  19.44 18.81 21.379 19.224 ;
     RECT  21.235 14.526 21.407 17.874 ;
     RECT  20.579 5.346 21.415 5.364 ;
     RECT  20.471 9.324 21.415 9.882 ;
     RECT  20.543 11.826 21.415 12.348 ;
     RECT  21.407 16.578 21.443 17.874 ;
     RECT  20.651 3.456 21.479 3.87 ;
     RECT  20.543 13.608 21.479 13.626 ;
     RECT  21.407 14.526 21.479 15.786 ;
     RECT  21.443 17.46 21.479 17.874 ;
     RECT  21.379 18.774 21.479 19.224 ;
     RECT  21.415 5.346 21.515 5.634 ;
     RECT  21.343 6.588 21.515 7.65 ;
     RECT  21.415 8.856 21.515 9.882 ;
     RECT  21.415 11.556 21.515 12.744 ;
     RECT  21.479 14.526 21.515 14.544 ;
     RECT  21.479 17.856 21.515 17.874 ;
     RECT  21.479 3.456 21.587 3.474 ;
     RECT  21.515 7.632 21.587 7.65 ;
     RECT  21.479 15.534 21.587 15.552 ;
     RECT  21.479 19.206 21.587 19.224 ;
    LAYER M3 ;
     RECT  5.796 1.921 5.814 1.993 ;
     RECT  7.596 1.921 7.614 2.011 ;
     RECT  4.608 1.993 4.626 2.029 ;
     RECT  7.488 2.011 7.614 2.029 ;
     RECT  4.392 2.029 4.626 2.101 ;
     RECT  10.26 2.065 10.278 2.101 ;
     RECT  16.524 2.029 16.542 2.101 ;
     RECT  20.232 2.029 20.25 2.101 ;
     RECT  2.988 2.029 3.006 2.143 ;
     RECT  4.32 2.101 4.626 2.143 ;
     RECT  5.796 1.993 6.318 2.143 ;
     RECT  7.416 2.029 7.614 2.143 ;
     RECT  10.26 2.101 10.35 2.143 ;
     RECT  15.624 2.101 15.642 2.143 ;
     RECT  16.524 2.101 17.226 2.143 ;
     RECT  18.144 2.101 18.162 2.143 ;
     RECT  10.26 2.143 10.605 2.191 ;
     RECT  15.624 2.143 17.226 2.219 ;
     RECT  18.144 2.143 18.705 2.227 ;
     RECT  2.415 2.143 3.006 2.251 ;
     RECT  4.32 2.143 6.318 2.251 ;
     RECT  7.416 2.143 7.905 2.293 ;
     RECT  4.32 2.251 6.462 2.299 ;
     RECT  7.416 2.293 7.974 2.299 ;
     RECT  18.144 2.227 19.026 2.299 ;
     RECT  19.944 2.101 20.25 2.299 ;
     RECT  4.248 2.299 6.498 2.335 ;
     RECT  7.38 2.299 7.974 2.335 ;
     RECT  8.964 2.227 8.982 2.335 ;
     RECT  10.26 2.191 11.106 2.335 ;
     RECT  18.144 2.299 20.25 2.335 ;
     RECT  13.215 2.143 13.305 2.413 ;
     RECT  14.292 2.371 14.31 2.489 ;
     RECT  4.14 2.335 8.982 2.569 ;
     RECT  9.756 2.335 11.106 2.569 ;
     RECT  15.732 2.219 17.226 2.569 ;
     RECT  18.108 2.335 20.25 2.569 ;
     RECT  2.415 2.251 3.366 2.605 ;
     RECT  2.304 2.605 3.366 2.641 ;
     RECT  4.14 2.569 11.106 2.641 ;
     RECT  14.832 2.569 14.85 3.001 ;
     RECT  15.732 2.569 20.25 3.001 ;
     RECT  11.952 2.029 11.97 3.073 ;
     RECT  14.832 3.001 20.25 3.073 ;
     RECT  11.88 3.073 11.97 3.109 ;
     RECT  2.304 2.641 11.106 3.211 ;
     RECT  11.88 3.109 12.078 3.299 ;
     RECT  1.98 3.211 11.106 3.307 ;
     RECT  11.88 3.299 11.898 3.307 ;
     RECT  1.98 3.307 11.898 3.371 ;
     RECT  1.98 3.371 11.826 3.416 ;
     RECT  1.98 3.416 11.79 3.569 ;
     RECT  13.215 2.413 13.497 3.613 ;
     RECT  14.832 3.073 20.574 3.685 ;
     RECT  21.564 3.451 21.582 3.691 ;
     RECT  14.58 3.685 20.574 3.721 ;
     RECT  21.492 3.691 21.582 3.847 ;
     RECT  1.98 3.569 11.718 4.253 ;
     RECT  14.58 3.721 20.682 4.261 ;
     RECT  13.215 3.613 13.554 4.351 ;
     RECT  0.108 2.227 0.126 4.363 ;
     RECT  13.104 4.351 13.554 4.397 ;
     RECT  21.456 3.847 21.582 4.555 ;
     RECT  2.268 4.253 11.718 4.649 ;
     RECT  13.215 4.397 13.554 4.729 ;
     RECT  14.364 4.261 20.682 4.729 ;
     RECT  21.42 4.555 21.582 4.733 ;
     RECT  2.268 4.649 10.854 4.757 ;
     RECT  13.215 4.729 20.682 4.973 ;
     RECT  0.108 4.363 0.342 5.035 ;
     RECT  1.152 2.443 1.17 5.035 ;
     RECT  13.215 4.973 19.206 5.189 ;
     RECT  0.108 5.035 1.17 5.419 ;
     RECT  2.304 4.757 10.854 5.467 ;
     RECT  11.7 4.649 11.718 5.467 ;
     RECT  21.456 4.733 21.582 5.563 ;
     RECT  0.108 5.419 1.242 5.597 ;
     RECT  21.42 5.563 21.582 5.639 ;
     RECT  21.492 5.639 21.582 5.648 ;
     RECT  13.215 5.189 19.17 5.707 ;
     RECT  2.304 5.467 11.718 5.729 ;
     RECT  19.98 4.973 20.682 5.773 ;
     RECT  0.108 5.597 0.558 6.221 ;
     RECT  19.944 5.773 20.682 6.221 ;
     RECT  19.944 6.221 20.574 6.317 ;
     RECT  13.104 5.707 19.17 6.413 ;
     RECT  13.176 6.413 19.17 6.421 ;
     RECT  19.944 6.317 20.502 6.421 ;
     RECT  2.304 5.729 10.998 6.571 ;
     RECT  21.564 5.648 21.582 6.571 ;
     RECT  21.492 6.571 21.582 6.781 ;
     RECT  21.42 6.781 21.582 6.845 ;
     RECT  0.108 6.221 0.342 6.893 ;
     RECT  0.18 6.893 0.342 7.159 ;
     RECT  13.176 6.421 20.502 7.181 ;
     RECT  1.98 6.571 10.998 7.231 ;
     RECT  1.98 7.231 11.106 7.349 ;
     RECT  20.016 7.181 20.502 7.373 ;
     RECT  10.188 7.349 10.89 7.421 ;
     RECT  13.176 7.181 19.17 7.429 ;
     RECT  20.484 7.373 20.502 7.501 ;
     RECT  21.456 6.845 21.582 7.627 ;
     RECT  21.348 7.627 21.582 7.655 ;
     RECT  20.484 7.501 20.538 7.663 ;
     RECT  21.348 7.655 21.51 7.664 ;
     RECT  13.104 7.429 19.17 7.771 ;
     RECT  21.42 7.664 21.51 7.853 ;
     RECT  12.888 7.771 19.17 7.889 ;
     RECT  0.18 7.159 0.558 7.933 ;
     RECT  0.108 7.933 0.558 8.011 ;
     RECT  13.104 7.889 19.17 8.041 ;
     RECT  1.98 7.349 9.378 8.239 ;
     RECT  10.188 7.421 10.818 8.239 ;
     RECT  1.98 8.239 10.818 8.251 ;
     RECT  20.484 7.663 20.574 8.311 ;
     RECT  13.104 8.041 19.422 8.333 ;
     RECT  0.108 8.011 1.17 8.621 ;
     RECT  20.484 8.311 20.61 8.621 ;
     RECT  1.98 8.251 10.926 8.731 ;
     RECT  13.104 8.333 19.17 8.735 ;
     RECT  20.484 8.621 20.502 8.779 ;
     RECT  21.492 7.853 21.51 8.827 ;
     RECT  0.144 8.621 1.17 8.909 ;
     RECT  20.448 8.779 20.502 9.067 ;
     RECT  1.98 8.731 11.322 9.085 ;
     RECT  20.412 9.067 20.502 9.355 ;
     RECT  1.98 9.085 11.43 9.383 ;
     RECT  20.412 9.355 20.538 9.581 ;
     RECT  20.412 9.581 20.502 9.643 ;
     RECT  0.504 8.909 1.17 9.773 ;
     RECT  2.268 9.383 10.998 9.779 ;
     RECT  21.42 8.827 21.51 9.787 ;
     RECT  1.152 9.773 1.17 9.883 ;
     RECT  2.268 9.779 9.234 9.887 ;
     RECT  21.348 9.787 21.51 9.887 ;
     RECT  13.104 8.735 19.134 10.021 ;
     RECT  1.152 9.883 1.206 10.061 ;
     RECT  0.144 9.931 0.162 10.109 ;
     RECT  20.196 9.643 20.502 10.219 ;
     RECT  21.348 9.887 21.438 10.363 ;
     RECT  10.224 9.779 10.998 10.4 ;
     RECT  1.152 10.061 1.17 10.427 ;
     RECT  13.068 10.021 19.134 10.471 ;
     RECT  21.312 10.363 21.438 10.541 ;
     RECT  10.224 10.4 10.926 10.589 ;
     RECT  2.304 9.887 9.234 10.651 ;
     RECT  12.564 10.471 19.134 10.741 ;
     RECT  2.304 10.651 9.342 10.795 ;
     RECT  2.232 10.795 9.342 10.831 ;
     RECT  10.224 10.589 10.797 10.831 ;
     RECT  12.492 10.741 19.134 10.891 ;
     RECT  19.908 10.219 20.502 10.891 ;
     RECT  2.232 10.831 10.797 10.903 ;
     RECT  12.492 10.891 20.502 11.011 ;
     RECT  21.348 10.541 21.438 11.021 ;
     RECT  0.324 10.507 0.342 11.083 ;
     RECT  0.324 11.083 0.378 11.131 ;
     RECT  0.216 11.131 0.378 11.213 ;
     RECT  12.456 11.011 20.538 11.273 ;
     RECT  12.492 11.273 20.538 11.309 ;
     RECT  0.216 11.213 0.306 11.405 ;
     RECT  21.42 11.021 21.438 11.551 ;
     RECT  2.16 10.903 10.797 11.749 ;
     RECT  12.492 11.309 19.206 11.849 ;
     RECT  20.448 11.309 20.538 12.043 ;
     RECT  2.16 11.749 10.89 12.055 ;
     RECT  21.42 11.551 21.51 12.136 ;
     RECT  21.384 12.136 21.51 12.221 ;
     RECT  2.16 12.055 10.962 12.253 ;
     RECT  0.108 11.785 0.126 12.325 ;
     RECT  20.376 12.043 20.538 12.461 ;
     RECT  12.528 11.849 19.206 12.523 ;
     RECT  0.108 12.325 0.558 12.557 ;
     RECT  2.16 12.253 11.43 12.623 ;
     RECT  2.268 12.623 11.43 12.631 ;
     RECT  0.144 12.557 0.558 12.653 ;
     RECT  2.268 12.631 11.538 12.749 ;
     RECT  12.528 12.523 19.674 12.749 ;
     RECT  12.564 12.749 19.674 12.929 ;
     RECT  0.144 12.653 0.162 13.037 ;
     RECT  2.268 12.749 11.43 13.133 ;
     RECT  20.52 12.461 20.538 13.195 ;
     RECT  20.412 13.195 20.538 13.421 ;
     RECT  2.268 13.133 11.034 13.469 ;
     RECT  12.6 12.929 19.674 13.675 ;
     RECT  12.6 13.675 20.214 13.703 ;
     RECT  2.268 13.469 10.926 14.011 ;
     RECT  21.42 12.221 21.51 14.059 ;
     RECT  2.232 14.011 10.926 14.099 ;
     RECT  12.096 13.981 12.114 14.143 ;
     RECT  12.024 14.143 12.114 14.171 ;
     RECT  10.515 14.099 10.926 14.207 ;
     RECT  12.96 13.703 20.214 14.251 ;
     RECT  2.232 14.099 9.522 14.279 ;
     RECT  12.96 14.251 20.538 14.381 ;
     RECT  0.324 13.483 0.342 14.443 ;
     RECT  21.348 14.059 21.51 14.539 ;
     RECT  0.108 14.443 0.342 14.669 ;
     RECT  0.108 14.669 0.126 14.765 ;
     RECT  2.304 14.279 9.522 14.881 ;
     RECT  10.515 14.207 10.797 14.881 ;
     RECT  12.96 14.381 20.286 15.115 ;
     RECT  12.024 14.171 12.042 15.179 ;
     RECT  12.96 15.115 20.502 15.493 ;
     RECT  21.276 14.539 21.51 15.529 ;
     RECT  2.304 14.881 10.797 15.557 ;
     RECT  12.888 15.493 20.502 15.565 ;
     RECT  12.816 15.565 20.502 15.719 ;
     RECT  21.276 15.529 21.582 15.739 ;
     RECT  21.24 15.739 21.582 15.791 ;
     RECT  12.96 15.719 20.502 15.899 ;
     RECT  2.415 15.557 10.797 16.069 ;
     RECT  13.104 15.899 20.502 16.133 ;
     RECT  21.276 15.791 21.582 16.301 ;
     RECT  13.215 16.133 20.502 16.541 ;
     RECT  2.415 16.069 10.854 16.645 ;
     RECT  14.22 16.541 20.502 16.673 ;
     RECT  2.304 16.645 10.854 16.771 ;
     RECT  2.304 16.771 11.142 16.871 ;
     RECT  14.22 16.673 20.466 17.069 ;
     RECT  0.144 16.807 0.162 17.077 ;
     RECT  0.108 17.077 0.162 17.165 ;
     RECT  0.144 17.165 0.162 17.261 ;
     RECT  13.215 16.541 13.497 17.347 ;
     RECT  14.22 17.069 20.286 17.347 ;
     RECT  2.304 16.871 11.034 17.681 ;
     RECT  13.215 17.347 20.286 17.761 ;
     RECT  3.888 17.681 11.034 17.923 ;
     RECT  12.996 17.761 20.286 17.989 ;
     RECT  3.888 17.923 11.07 18.029 ;
     RECT  12.456 17.989 20.286 18.029 ;
     RECT  3.888 18.029 7.038 18.059 ;
     RECT  14.652 18.029 20.286 18.077 ;
     RECT  3.96 18.059 7.038 18.149 ;
     RECT  9.108 18.029 11.07 18.149 ;
     RECT  12.456 18.029 13.806 18.149 ;
     RECT  2.304 17.681 2.97 18.185 ;
     RECT  4.932 18.149 6.714 18.185 ;
     RECT  10.008 18.149 10.998 18.221 ;
     RECT  12.204 18.184 12.222 18.221 ;
     RECT  13.215 18.149 13.734 18.221 ;
     RECT  9.108 18.149 9.126 18.419 ;
     RECT  10.152 18.221 10.998 18.455 ;
     RECT  10.152 18.455 10.797 18.491 ;
     RECT  15.048 18.077 20.286 18.725 ;
     RECT  21.384 16.301 21.582 18.797 ;
     RECT  15.048 18.725 17.55 18.805 ;
     RECT  5.115 18.185 5.994 18.833 ;
     RECT  21.456 18.797 21.582 18.833 ;
     RECT  18.324 18.725 20.286 18.869 ;
     RECT  14.832 18.805 17.55 18.995 ;
     RECT  18.324 18.869 19.098 19.031 ;
     RECT  14.832 18.995 17.118 19.067 ;
     RECT  18.576 19.031 19.098 19.067 ;
     RECT  20.196 18.869 20.286 19.067 ;
     RECT  14.832 19.067 14.85 19.139 ;
     RECT  20.268 19.067 20.286 19.139 ;
     RECT  2.415 18.185 2.697 19.187 ;
     RECT  5.115 18.833 5.397 19.187 ;
     RECT  7.815 18.029 8.097 19.187 ;
     RECT  10.515 18.491 10.797 19.187 ;
     RECT  13.215 18.221 13.497 19.187 ;
     RECT  15.915 19.067 17.118 19.229 ;
     RECT  18.615 19.067 19.098 19.229 ;
     RECT  21.564 18.833 21.582 19.229 ;
     RECT  16.848 19.229 16.866 19.301 ;
     RECT  18.615 19.229 18.774 19.301 ;
     RECT  18.615 19.301 18.738 19.373 ;
     RECT  2.415 19.187 2.505 19.457 ;
     RECT  5.115 19.187 5.205 19.457 ;
     RECT  7.815 19.187 7.905 19.457 ;
     RECT  10.515 19.187 10.605 19.457 ;
     RECT  13.215 19.187 13.305 19.457 ;
     RECT  15.915 19.229 16.005 19.457 ;
     RECT  18.615 19.373 18.705 19.457 ;
    LAYER M4 ;
     RECT  0.084 2.448 0.097 2.472 ;
     RECT  0.06 2.472 0.097 2.544 ;
     RECT  0.084 2.544 0.097 2.568 ;
     RECT  0.06 2.568 0.097 2.64 ;
     RECT  0.084 2.64 0.097 2.664 ;
     RECT  0.06 2.664 0.097 2.736 ;
     RECT  0.084 2.736 0.097 2.76 ;
     RECT  0.06 2.76 0.097 2.832 ;
     RECT  0.084 2.832 0.097 2.856 ;
     RECT  0.06 2.856 0.097 2.928 ;
     RECT  0.084 2.928 0.097 2.952 ;
     RECT  0.06 2.952 0.097 3.024 ;
     RECT  0.084 3.024 0.097 3.048 ;
     RECT  0.06 3.048 0.097 3.12 ;
     RECT  0.084 3.12 0.097 3.144 ;
     RECT  0.06 3.144 0.097 3.216 ;
     RECT  0.084 3.216 0.097 3.24 ;
     RECT  0.06 3.24 0.097 3.312 ;
     RECT  0.084 3.312 0.097 3.336 ;
     RECT  0.06 3.336 0.097 3.408 ;
     RECT  0.084 3.408 0.097 3.432 ;
     RECT  0.06 3.432 0.097 3.504 ;
     RECT  0.084 3.504 0.097 3.528 ;
     RECT  0.06 3.528 0.097 3.6 ;
     RECT  0.084 3.6 0.097 3.624 ;
     RECT  0.06 3.624 0.097 3.696 ;
     RECT  0.084 3.696 0.097 3.72 ;
     RECT  0.06 3.72 0.097 3.792 ;
     RECT  0.084 3.792 0.097 3.816 ;
     RECT  0.06 3.816 0.097 3.888 ;
     RECT  0.084 3.888 0.097 3.912 ;
     RECT  0.06 3.912 0.097 3.984 ;
     RECT  0.084 3.984 0.097 4.008 ;
     RECT  0.06 4.008 0.097 4.08 ;
     RECT  0.084 4.08 0.097 4.104 ;
     RECT  0.06 4.104 0.097 4.176 ;
     RECT  0.084 4.176 0.097 4.2 ;
     RECT  0.06 4.2 0.097 4.272 ;
     RECT  0.084 4.272 0.097 4.296 ;
     RECT  0.06 4.296 0.097 4.368 ;
     RECT  0.084 4.368 0.097 4.392 ;
     RECT  0.06 4.392 0.097 4.464 ;
     RECT  0.084 4.464 0.097 4.488 ;
     RECT  0.06 4.488 0.097 4.56 ;
     RECT  0.084 4.56 0.097 4.584 ;
     RECT  0.06 4.584 0.097 4.656 ;
     RECT  0.084 4.656 0.097 4.68 ;
     RECT  0.06 4.68 0.097 4.752 ;
     RECT  0.084 4.752 0.097 4.776 ;
     RECT  0.06 4.776 0.097 4.848 ;
     RECT  0.084 4.848 0.097 4.872 ;
     RECT  0.06 4.872 0.097 4.944 ;
     RECT  0.084 4.944 0.097 4.968 ;
     RECT  0.06 4.968 0.097 5.04 ;
     RECT  0.084 5.04 0.097 5.064 ;
     RECT  0.06 5.064 0.097 5.136 ;
     RECT  0.084 5.136 0.097 5.16 ;
     RECT  0.06 5.16 0.097 5.232 ;
     RECT  0.084 5.232 0.097 5.256 ;
     RECT  0.06 5.256 0.097 5.328 ;
     RECT  0.084 5.328 0.097 5.352 ;
     RECT  0.06 5.352 0.097 5.424 ;
     RECT  0.084 5.424 0.097 5.448 ;
     RECT  0.06 5.448 0.097 5.52 ;
     RECT  0.084 5.52 0.097 5.544 ;
     RECT  0.06 5.544 0.097 5.616 ;
     RECT  0.084 5.616 0.097 5.64 ;
     RECT  0.06 5.64 0.097 5.712 ;
     RECT  0.084 5.712 0.097 5.736 ;
     RECT  0.06 5.736 0.097 5.808 ;
     RECT  0.084 5.808 0.097 5.832 ;
     RECT  0.06 5.832 0.097 5.904 ;
     RECT  0.084 5.904 0.097 5.928 ;
     RECT  0.06 5.928 0.097 6 ;
     RECT  0.084 6 0.097 6.024 ;
     RECT  0.06 6.024 0.097 6.096 ;
     RECT  0.084 6.096 0.097 6.12 ;
     RECT  0.06 6.12 0.097 6.192 ;
     RECT  0.084 6.192 0.097 6.216 ;
     RECT  0.06 6.216 0.097 6.288 ;
     RECT  0.084 6.288 0.097 6.312 ;
     RECT  0.06 6.312 0.097 6.384 ;
     RECT  0.084 6.384 0.097 6.408 ;
     RECT  0.06 6.408 0.097 6.48 ;
     RECT  0.084 6.48 0.097 6.504 ;
     RECT  0.06 6.504 0.097 6.576 ;
     RECT  0.084 6.576 0.097 6.6 ;
     RECT  0.06 6.6 0.097 6.672 ;
     RECT  0.084 6.672 0.097 6.696 ;
     RECT  0.06 6.696 0.097 6.768 ;
     RECT  0.084 6.768 0.097 6.792 ;
     RECT  0.06 6.792 0.097 6.864 ;
     RECT  0.084 6.864 0.097 6.888 ;
     RECT  0.06 6.888 0.097 6.96 ;
     RECT  0.084 6.96 0.097 6.984 ;
     RECT  0.06 6.984 0.097 7.056 ;
     RECT  0.084 7.056 0.097 7.08 ;
     RECT  0.06 7.08 0.097 7.152 ;
     RECT  0.084 7.152 0.097 7.176 ;
     RECT  0.06 7.176 0.097 7.248 ;
     RECT  0.084 7.248 0.097 7.272 ;
     RECT  0.06 7.272 0.097 7.344 ;
     RECT  0.084 7.344 0.097 7.368 ;
     RECT  0.06 7.368 0.097 7.44 ;
     RECT  0.084 7.44 0.097 7.464 ;
     RECT  0.06 7.464 0.097 7.536 ;
     RECT  0.084 7.536 0.097 7.56 ;
     RECT  0.06 7.56 0.097 7.632 ;
     RECT  0.084 7.632 0.097 7.656 ;
     RECT  0.06 7.656 0.097 7.728 ;
     RECT  0.084 7.728 0.097 7.752 ;
     RECT  0.06 7.752 0.097 7.824 ;
     RECT  0.084 7.824 0.097 7.848 ;
     RECT  0.06 7.848 0.097 7.92 ;
     RECT  0.084 7.92 0.097 7.944 ;
     RECT  0.06 7.944 0.097 8.016 ;
     RECT  0.084 8.016 0.097 8.04 ;
     RECT  0.06 8.04 0.097 8.112 ;
     RECT  0.084 8.112 0.097 8.136 ;
     RECT  0.06 8.136 0.097 8.208 ;
     RECT  0.084 8.208 0.097 8.232 ;
     RECT  0.06 8.232 0.097 8.304 ;
     RECT  0.084 8.304 0.097 8.328 ;
     RECT  0.06 8.328 0.097 8.4 ;
     RECT  0.084 8.4 0.097 8.424 ;
     RECT  0.06 8.424 0.097 8.496 ;
     RECT  0.084 8.496 0.097 8.52 ;
     RECT  0.06 8.52 0.097 8.592 ;
     RECT  0.084 8.592 0.097 8.616 ;
     RECT  0.06 8.616 0.097 8.688 ;
     RECT  0.084 8.688 0.097 8.712 ;
     RECT  0.06 8.712 0.097 8.784 ;
     RECT  0.084 8.784 0.097 8.808 ;
     RECT  0.06 8.808 0.097 8.88 ;
     RECT  0.084 8.88 0.097 8.904 ;
     RECT  0.06 8.904 0.097 8.976 ;
     RECT  0.084 8.976 0.097 9 ;
     RECT  0.06 9 0.097 9.072 ;
     RECT  0.084 9.072 0.097 9.096 ;
     RECT  0.06 9.096 0.097 9.168 ;
     RECT  0.084 9.168 0.097 9.192 ;
     RECT  0.06 9.192 0.097 9.264 ;
     RECT  0.084 9.264 0.097 9.288 ;
     RECT  0.06 9.288 0.097 9.36 ;
     RECT  0.084 9.36 0.097 9.384 ;
     RECT  0.06 9.384 0.097 9.456 ;
     RECT  0.084 9.456 0.097 9.48 ;
     RECT  0.06 9.48 0.097 9.552 ;
     RECT  0.084 9.552 0.097 9.576 ;
     RECT  0.06 9.576 0.097 9.648 ;
     RECT  0.084 9.648 0.097 9.672 ;
     RECT  0.06 9.672 0.097 9.744 ;
     RECT  0.084 9.744 0.097 9.768 ;
     RECT  0.06 9.768 0.097 9.84 ;
     RECT  0.084 9.84 0.097 9.864 ;
     RECT  0.06 9.864 0.097 9.936 ;
     RECT  0.084 9.936 0.097 9.96 ;
     RECT  0.06 9.96 0.097 10.032 ;
     RECT  0.084 10.032 0.097 10.056 ;
     RECT  0.06 10.056 0.097 10.128 ;
     RECT  0.084 10.128 0.097 10.152 ;
     RECT  0.06 10.152 0.097 10.224 ;
     RECT  0.084 10.224 0.097 10.248 ;
     RECT  0.06 10.248 0.097 10.32 ;
     RECT  0.084 10.32 0.097 10.344 ;
     RECT  0.06 10.344 0.097 10.416 ;
     RECT  0.084 10.416 0.097 10.44 ;
     RECT  0.06 10.44 0.097 10.512 ;
     RECT  0.084 10.512 0.097 10.536 ;
     RECT  0.06 10.536 0.097 10.608 ;
     RECT  0.084 10.608 0.097 10.632 ;
     RECT  0.06 10.632 0.097 10.704 ;
     RECT  0.084 10.704 0.097 10.728 ;
     RECT  0.06 10.728 0.097 10.8 ;
     RECT  0.084 10.8 0.097 10.824 ;
     RECT  0.06 10.824 0.097 10.896 ;
     RECT  0.084 10.896 0.097 10.92 ;
     RECT  0.06 10.92 0.097 10.992 ;
     RECT  0.084 10.992 0.097 11.016 ;
     RECT  0.06 11.016 0.097 11.088 ;
     RECT  0.084 11.088 0.097 11.112 ;
     RECT  0.06 11.112 0.097 11.184 ;
     RECT  0.084 11.184 0.097 11.208 ;
     RECT  0.06 11.208 0.097 11.28 ;
     RECT  0.084 11.28 0.097 11.304 ;
     RECT  0.06 11.304 0.097 11.376 ;
     RECT  0.084 11.376 0.097 11.4 ;
     RECT  0.06 11.4 0.097 11.472 ;
     RECT  0.084 11.472 0.097 11.496 ;
     RECT  0.06 11.496 0.097 11.568 ;
     RECT  0.084 11.568 0.097 11.592 ;
     RECT  0.06 11.592 0.097 11.664 ;
     RECT  0.084 11.664 0.097 11.688 ;
     RECT  0.06 11.688 0.097 11.76 ;
     RECT  0.084 11.76 0.097 11.784 ;
     RECT  0.06 11.784 0.097 11.856 ;
     RECT  0.084 11.856 0.097 11.88 ;
     RECT  0.06 11.88 0.097 11.952 ;
     RECT  0.084 11.952 0.097 11.976 ;
     RECT  0.06 11.976 0.097 12.048 ;
     RECT  0.084 12.048 0.097 12.072 ;
     RECT  0.06 12.072 0.097 12.144 ;
     RECT  0.084 12.144 0.097 12.168 ;
     RECT  0.06 12.168 0.097 12.24 ;
     RECT  0.084 12.24 0.097 12.264 ;
     RECT  0.06 12.264 0.097 12.336 ;
     RECT  0.084 12.336 0.097 12.36 ;
     RECT  0.06 12.36 0.097 12.432 ;
     RECT  0.084 12.432 0.097 12.456 ;
     RECT  0.06 12.456 0.097 12.528 ;
     RECT  0.084 12.528 0.097 12.552 ;
     RECT  0.06 12.552 0.097 12.624 ;
     RECT  0.084 12.624 0.097 12.648 ;
     RECT  0.06 12.648 0.097 12.72 ;
     RECT  0.084 12.72 0.097 12.744 ;
     RECT  0.06 12.744 0.097 12.816 ;
     RECT  0.084 12.816 0.097 12.84 ;
     RECT  0.06 12.84 0.097 12.912 ;
     RECT  0.084 12.912 0.097 12.936 ;
     RECT  0.06 12.936 0.097 13.008 ;
     RECT  0.084 13.008 0.097 13.032 ;
     RECT  0.06 13.032 0.097 13.104 ;
     RECT  0.084 13.104 0.097 13.128 ;
     RECT  0.06 13.128 0.097 13.2 ;
     RECT  0.084 13.2 0.097 13.224 ;
     RECT  0.06 13.224 0.097 13.296 ;
     RECT  0.084 13.296 0.097 13.32 ;
     RECT  0.06 13.32 0.097 13.392 ;
     RECT  0.084 13.392 0.097 13.416 ;
     RECT  0.06 13.416 0.097 13.488 ;
     RECT  0.084 13.488 0.097 13.512 ;
     RECT  0.06 13.512 0.097 13.584 ;
     RECT  0.084 13.584 0.097 13.608 ;
     RECT  0.06 13.608 0.097 13.68 ;
     RECT  0.084 13.68 0.097 13.704 ;
     RECT  0.06 13.704 0.097 13.776 ;
     RECT  0.084 13.776 0.097 13.8 ;
     RECT  0.06 13.8 0.097 13.872 ;
     RECT  0.084 13.872 0.097 13.896 ;
     RECT  0.06 13.896 0.097 13.968 ;
     RECT  0.084 13.968 0.097 13.992 ;
     RECT  0.06 13.992 0.097 14.064 ;
     RECT  0.084 14.064 0.097 14.088 ;
     RECT  0.06 14.088 0.097 14.16 ;
     RECT  0.084 14.16 0.097 14.184 ;
     RECT  0.06 14.184 0.097 14.256 ;
     RECT  0.084 14.256 0.097 14.28 ;
     RECT  0.06 14.28 0.097 14.352 ;
     RECT  0.084 14.352 0.097 14.376 ;
     RECT  0.06 14.376 0.097 14.448 ;
     RECT  0.084 14.448 0.097 14.472 ;
     RECT  0.06 14.472 0.097 14.544 ;
     RECT  0.084 14.544 0.097 14.568 ;
     RECT  0.06 14.568 0.097 14.64 ;
     RECT  0.084 14.64 0.097 14.664 ;
     RECT  0.097 2.448 0.133 14.76 ;
     RECT  0.133 2.448 1.181 14.808 ;
     RECT  1.181 2.544 2.408 14.808 ;
     RECT  0.084 16.944 2.408 16.968 ;
     RECT  0.06 16.968 2.408 17.04 ;
     RECT  0.084 17.04 2.408 17.064 ;
     RECT  0.06 17.064 2.408 17.136 ;
     RECT  0.084 17.136 2.408 17.16 ;
     RECT  0.06 17.16 2.408 17.232 ;
     RECT  0.084 17.232 2.408 17.256 ;
     RECT  0.06 17.256 2.408 17.328 ;
     RECT  0.084 17.328 2.408 17.352 ;
     RECT  0.06 17.352 2.408 17.424 ;
     RECT  0.084 17.424 2.408 17.448 ;
     RECT  0.06 17.448 2.408 17.52 ;
     RECT  0.084 17.52 2.408 17.544 ;
     RECT  0.06 17.544 2.408 17.616 ;
     RECT  0.084 17.616 2.408 17.64 ;
     RECT  0.06 17.64 2.408 17.712 ;
     RECT  0.084 17.712 2.408 17.736 ;
     RECT  2.408 2.148 2.512 19.452 ;
     RECT  2.512 2.256 2.704 19.182 ;
     RECT  2.704 2.256 2.837 17.352 ;
     RECT  2.837 3.936 2.867 17.352 ;
     RECT  2.867 14.16 2.873 17.352 ;
     RECT  2.873 14.64 3.017 17.352 ;
     RECT  2.837 2.256 3.305 2.856 ;
     RECT  3.017 14.688 3.913 17.352 ;
     RECT  2.867 3.936 3.949 13.032 ;
     RECT  3.949 3.936 4.057 13.368 ;
     RECT  3.913 14.688 4.057 17.736 ;
     RECT  4.057 3.936 4.165 17.736 ;
     RECT  3.305 2.256 4.525 2.808 ;
     RECT  4.165 3.936 4.525 18.12 ;
     RECT  4.525 2.256 5.108 18.12 ;
     RECT  5.108 2.148 5.212 19.452 ;
     RECT  5.212 2.256 5.404 19.182 ;
     RECT  5.404 2.256 7.405 17.736 ;
     RECT  7.405 2.256 7.477 18.024 ;
     RECT  7.477 2.016 7.808 18.024 ;
     RECT  7.621 0.096 7.859 0.12 ;
     RECT  7.808 2.016 7.912 19.452 ;
     RECT  7.912 2.016 7.955 19.182 ;
     RECT  7.955 2.304 7.985 19.182 ;
     RECT  7.985 2.418 8.104 19.182 ;
     RECT  8.104 2.496 8.849 18.024 ;
     RECT  8.849 2.592 9.029 18.024 ;
     RECT  9.029 2.592 9.065 3.336 ;
     RECT  9.029 4.416 9.173 18.024 ;
     RECT  9.173 4.416 9.245 16.392 ;
     RECT  9.245 10.656 9.353 16.392 ;
     RECT  9.353 10.944 9.497 16.392 ;
     RECT  9.497 11.136 10.465 16.392 ;
     RECT  9.065 2.88 10.508 3.336 ;
     RECT  9.245 4.416 10.508 9.528 ;
     RECT  10.465 10.992 10.508 16.392 ;
     RECT  9.173 17.424 10.508 18.024 ;
     RECT  10.508 2.148 10.612 19.452 ;
     RECT  10.612 2.418 10.804 19.182 ;
     RECT  10.804 17.424 12.193 18.024 ;
     RECT  10.804 3.312 13.208 3.336 ;
     RECT  10.804 4.368 13.208 16.392 ;
     RECT  12.193 17.424 13.208 18.216 ;
     RECT  13.208 2.148 13.312 19.452 ;
     RECT  13.312 2.418 13.504 19.182 ;
     RECT  13.504 4.368 14.897 18.216 ;
     RECT  13.504 3.312 15.908 3.336 ;
     RECT  14.897 4.464 15.908 18.216 ;
     RECT  15.908 2.148 16.012 19.452 ;
     RECT  16.012 2.418 16.204 19.182 ;
     RECT  16.204 3.264 16.445 18.792 ;
     RECT  16.445 3.264 16.805 18.744 ;
     RECT  16.805 3.552 17.093 18.744 ;
     RECT  17.093 3.552 18.608 17.64 ;
     RECT  17.093 18.72 18.608 18.744 ;
     RECT  18.608 2.148 18.712 19.452 ;
     RECT  18.712 2.418 18.904 19.182 ;
     RECT  18.904 3.696 21.521 3.792 ;
     RECT  18.904 3.792 21.516 3.816 ;
     RECT  18.904 3.816 21.521 3.888 ;
     RECT  18.904 3.888 21.516 3.912 ;
     RECT  18.904 3.912 21.521 3.984 ;
     RECT  18.904 3.984 21.516 4.008 ;
     RECT  18.904 4.008 21.521 4.08 ;
     RECT  18.904 4.08 21.516 4.104 ;
     RECT  18.904 4.104 21.521 4.176 ;
     RECT  18.904 4.176 21.516 4.2 ;
     RECT  18.904 4.2 21.521 4.272 ;
     RECT  18.904 4.272 21.516 4.296 ;
     RECT  18.904 4.296 21.521 4.368 ;
     RECT  18.904 4.368 21.516 4.392 ;
     RECT  18.904 4.392 21.521 4.464 ;
     RECT  18.904 4.464 21.516 4.488 ;
     RECT  18.904 4.488 21.521 4.56 ;
     RECT  18.904 4.56 21.516 4.584 ;
     RECT  18.904 4.584 21.521 4.656 ;
     RECT  18.904 4.656 21.516 4.68 ;
     RECT  18.904 4.68 21.521 4.752 ;
     RECT  18.904 4.752 21.516 4.776 ;
     RECT  18.904 4.776 21.521 4.848 ;
     RECT  18.904 4.848 21.516 4.872 ;
     RECT  18.904 4.872 21.521 4.944 ;
     RECT  18.904 4.944 21.516 4.968 ;
     RECT  18.904 4.968 21.521 5.04 ;
     RECT  18.904 5.04 21.516 5.064 ;
     RECT  18.904 5.064 21.521 5.136 ;
     RECT  18.904 5.136 21.516 5.16 ;
     RECT  18.904 5.16 21.521 5.232 ;
     RECT  18.904 5.232 21.516 5.256 ;
     RECT  18.904 5.256 21.521 5.328 ;
     RECT  18.904 5.328 21.516 5.352 ;
     RECT  18.904 5.352 21.521 5.424 ;
     RECT  18.904 5.424 21.516 5.448 ;
     RECT  18.904 5.448 21.521 5.52 ;
     RECT  18.904 5.52 21.516 5.544 ;
     RECT  18.904 5.544 21.521 5.616 ;
     RECT  18.904 5.616 21.516 5.64 ;
     RECT  18.904 5.64 21.521 5.712 ;
     RECT  18.904 5.712 21.516 5.736 ;
     RECT  18.904 5.736 21.521 5.808 ;
     RECT  18.904 5.808 21.516 5.832 ;
     RECT  18.904 5.832 21.521 5.904 ;
     RECT  18.904 5.904 21.516 5.928 ;
     RECT  18.904 5.928 21.521 6 ;
     RECT  18.904 6 21.516 6.024 ;
     RECT  18.904 6.024 21.521 6.096 ;
     RECT  18.904 6.096 21.516 6.12 ;
     RECT  18.904 6.12 21.521 6.192 ;
     RECT  18.904 6.192 21.516 6.216 ;
     RECT  18.904 6.216 21.521 6.288 ;
     RECT  18.904 6.288 21.516 6.312 ;
     RECT  18.904 6.312 21.521 6.384 ;
     RECT  18.904 6.384 21.516 6.408 ;
     RECT  18.904 6.408 21.521 6.48 ;
     RECT  18.904 6.48 21.516 6.504 ;
     RECT  18.904 6.504 21.521 6.576 ;
     RECT  18.904 6.576 21.516 6.6 ;
     RECT  18.904 6.6 21.521 6.672 ;
     RECT  18.904 6.672 21.516 6.696 ;
     RECT  18.904 6.696 21.521 6.768 ;
     RECT  18.904 6.768 21.516 6.792 ;
     RECT  18.904 6.792 21.521 6.864 ;
     RECT  18.904 6.864 21.516 6.888 ;
     RECT  18.904 6.888 21.521 6.96 ;
     RECT  18.904 6.96 21.516 6.984 ;
     RECT  18.904 6.984 21.521 7.056 ;
     RECT  18.904 7.056 21.516 7.08 ;
     RECT  18.904 7.08 21.521 7.152 ;
     RECT  18.904 7.152 21.516 7.176 ;
     RECT  18.904 7.176 21.521 7.248 ;
     RECT  18.904 7.248 21.516 7.272 ;
     RECT  18.904 7.272 21.521 7.344 ;
     RECT  18.904 7.344 21.516 7.368 ;
     RECT  18.904 7.368 21.521 7.44 ;
     RECT  18.904 7.44 21.516 7.464 ;
     RECT  18.904 7.464 21.521 7.536 ;
     RECT  18.904 7.536 21.516 7.56 ;
     RECT  18.904 7.56 21.521 7.632 ;
     RECT  18.904 7.632 21.516 7.656 ;
     RECT  18.904 7.656 21.521 7.728 ;
     RECT  18.904 7.728 21.516 7.752 ;
     RECT  18.904 7.752 21.521 7.824 ;
     RECT  18.904 7.824 21.516 7.848 ;
     RECT  18.904 7.848 21.521 7.92 ;
     RECT  18.904 7.92 21.516 7.944 ;
     RECT  18.904 7.944 21.521 8.016 ;
     RECT  18.904 8.016 21.516 8.04 ;
     RECT  18.904 8.04 21.521 8.112 ;
     RECT  18.904 8.112 21.516 8.136 ;
     RECT  18.904 8.136 21.521 8.208 ;
     RECT  18.904 8.208 21.516 8.232 ;
     RECT  18.904 8.232 21.521 8.304 ;
     RECT  18.904 8.304 21.516 8.328 ;
     RECT  18.904 8.328 21.521 8.4 ;
     RECT  18.904 8.4 21.516 8.424 ;
     RECT  18.904 8.424 21.521 8.496 ;
     RECT  18.904 8.496 21.516 8.52 ;
     RECT  18.904 8.52 21.521 8.592 ;
     RECT  18.904 8.592 21.516 8.616 ;
     RECT  18.904 8.616 21.521 8.688 ;
     RECT  18.904 8.688 21.516 8.712 ;
     RECT  18.904 8.712 21.521 8.784 ;
     RECT  18.904 8.784 21.516 8.808 ;
     RECT  18.904 8.808 21.521 8.88 ;
     RECT  18.904 8.88 21.516 8.904 ;
     RECT  18.904 8.904 21.521 8.976 ;
     RECT  18.904 8.976 21.516 9 ;
     RECT  18.904 9 21.521 9.072 ;
     RECT  18.904 9.072 21.516 9.096 ;
     RECT  18.904 9.096 21.521 9.168 ;
     RECT  18.904 9.168 21.516 9.192 ;
     RECT  18.904 9.192 21.521 9.264 ;
     RECT  18.904 9.264 21.516 9.288 ;
     RECT  18.904 9.288 21.521 9.36 ;
     RECT  18.904 9.36 21.516 9.384 ;
     RECT  18.904 9.384 21.521 9.456 ;
     RECT  18.904 9.456 21.516 9.48 ;
     RECT  18.904 9.48 21.521 9.552 ;
     RECT  18.904 9.552 21.516 9.576 ;
     RECT  18.904 9.576 21.521 9.648 ;
     RECT  18.904 9.648 21.516 9.672 ;
     RECT  18.904 9.672 21.521 9.744 ;
     RECT  18.904 9.744 21.516 9.768 ;
     RECT  18.904 9.768 21.521 9.84 ;
     RECT  18.904 9.84 21.516 9.864 ;
     RECT  18.904 9.864 21.521 9.936 ;
     RECT  18.904 9.936 21.516 9.96 ;
     RECT  18.904 9.96 21.521 10.032 ;
     RECT  18.904 10.032 21.516 10.056 ;
     RECT  18.904 10.056 21.521 10.128 ;
     RECT  18.904 10.128 21.516 10.152 ;
     RECT  18.904 10.152 21.521 10.224 ;
     RECT  18.904 10.224 21.516 10.248 ;
     RECT  18.904 10.248 21.521 10.32 ;
     RECT  18.904 10.32 21.516 10.344 ;
     RECT  18.904 10.344 21.521 10.416 ;
     RECT  18.904 10.416 21.516 10.44 ;
     RECT  18.904 10.44 21.521 10.512 ;
     RECT  18.904 10.512 21.516 10.536 ;
     RECT  18.904 10.536 21.521 10.608 ;
     RECT  18.904 10.608 21.516 10.632 ;
     RECT  18.904 10.632 21.521 10.704 ;
     RECT  18.904 10.704 21.516 10.728 ;
     RECT  18.904 10.728 21.521 10.8 ;
     RECT  18.904 10.8 21.516 10.824 ;
     RECT  18.904 10.824 21.521 10.896 ;
     RECT  18.904 10.896 21.516 10.92 ;
     RECT  18.904 10.92 21.521 10.992 ;
     RECT  18.904 10.992 21.516 11.016 ;
     RECT  18.904 11.016 21.521 11.088 ;
     RECT  18.904 11.088 21.516 11.112 ;
     RECT  18.904 11.112 21.521 11.184 ;
     RECT  18.904 11.184 21.516 11.208 ;
     RECT  18.904 11.208 21.521 11.28 ;
     RECT  18.904 11.28 21.516 11.304 ;
     RECT  18.904 11.304 21.521 11.376 ;
     RECT  18.904 11.376 21.516 11.4 ;
     RECT  18.904 11.4 21.521 11.472 ;
     RECT  18.904 11.472 21.516 11.496 ;
     RECT  18.904 11.496 21.521 11.568 ;
     RECT  18.904 11.568 21.516 11.592 ;
     RECT  18.904 11.592 21.521 11.664 ;
     RECT  18.904 11.664 21.516 11.688 ;
     RECT  18.904 11.688 21.521 11.76 ;
     RECT  18.904 11.76 21.516 11.784 ;
     RECT  18.904 11.784 21.521 11.856 ;
     RECT  18.904 11.856 21.516 11.88 ;
     RECT  18.904 11.88 21.521 11.952 ;
     RECT  18.904 11.952 21.516 11.976 ;
     RECT  18.904 11.976 21.521 12.048 ;
     RECT  18.904 12.048 21.516 12.072 ;
     RECT  18.904 12.072 21.521 12.144 ;
     RECT  18.904 12.144 21.516 12.168 ;
     RECT  18.904 12.168 21.521 12.24 ;
     RECT  18.904 12.24 21.516 12.264 ;
     RECT  18.904 12.264 21.521 12.336 ;
     RECT  18.904 12.336 21.516 12.36 ;
     RECT  18.904 12.36 21.521 12.432 ;
     RECT  18.904 12.432 21.516 12.456 ;
     RECT  18.904 12.456 21.521 12.528 ;
     RECT  18.904 12.528 21.516 12.552 ;
     RECT  18.904 12.552 21.521 12.624 ;
     RECT  18.904 12.624 21.516 12.648 ;
     RECT  18.904 12.648 21.521 12.72 ;
     RECT  18.904 12.72 21.516 12.744 ;
     RECT  18.904 12.744 21.521 12.816 ;
     RECT  18.904 12.816 21.516 12.84 ;
     RECT  18.904 12.84 21.521 12.912 ;
     RECT  18.904 12.912 21.516 12.936 ;
     RECT  18.904 12.936 21.521 13.008 ;
     RECT  18.904 13.008 21.516 13.032 ;
     RECT  18.904 13.032 21.521 13.104 ;
     RECT  18.904 13.104 21.516 13.128 ;
     RECT  18.904 13.128 21.521 13.2 ;
     RECT  18.904 13.2 21.516 13.224 ;
     RECT  18.904 13.224 21.521 13.296 ;
     RECT  18.904 13.296 21.516 13.32 ;
     RECT  18.904 13.32 21.521 13.392 ;
     RECT  18.904 13.392 21.516 13.416 ;
     RECT  18.904 13.416 21.521 13.488 ;
     RECT  18.904 13.488 21.516 13.512 ;
     RECT  18.904 13.512 21.521 13.584 ;
     RECT  18.904 13.584 21.516 13.608 ;
     RECT  18.904 13.608 21.521 13.68 ;
     RECT  18.904 13.68 21.516 13.704 ;
     RECT  18.904 13.704 21.521 13.776 ;
     RECT  18.904 13.776 21.516 13.8 ;
     RECT  18.904 13.8 21.521 13.872 ;
     RECT  18.904 13.872 21.516 13.896 ;
     RECT  18.904 13.896 21.521 13.968 ;
     RECT  18.904 13.968 21.516 13.992 ;
     RECT  18.904 13.992 21.521 14.064 ;
     RECT  18.904 14.064 21.516 14.088 ;
     RECT  18.904 14.088 21.521 14.16 ;
     RECT  18.904 14.16 21.516 14.184 ;
     RECT  18.904 14.184 21.521 14.256 ;
     RECT  18.904 14.256 21.516 14.28 ;
     RECT  18.904 14.28 21.521 14.352 ;
     RECT  18.904 14.352 21.516 14.376 ;
     RECT  18.904 14.376 21.521 14.448 ;
     RECT  18.904 14.448 21.516 14.472 ;
     RECT  18.904 14.472 21.521 14.544 ;
     RECT  18.904 14.544 21.516 14.568 ;
     RECT  18.904 14.568 21.521 14.64 ;
     RECT  18.904 14.64 21.516 14.664 ;
     RECT  18.904 14.664 21.521 14.736 ;
     RECT  18.904 14.736 21.516 14.76 ;
     RECT  18.904 14.76 21.521 14.832 ;
     RECT  18.904 14.832 21.516 14.856 ;
     RECT  18.904 14.856 21.521 14.928 ;
     RECT  18.904 14.928 21.516 14.952 ;
     RECT  18.904 14.952 21.521 15.024 ;
     RECT  18.904 15.024 21.516 15.048 ;
     RECT  18.904 15.048 21.521 15.12 ;
     RECT  18.904 15.12 21.516 15.144 ;
     RECT  18.904 15.144 21.521 15.216 ;
     RECT  18.904 15.216 21.516 15.24 ;
     RECT  18.904 15.24 21.521 15.312 ;
     RECT  18.904 15.312 21.516 15.336 ;
     RECT  18.904 15.336 21.521 15.408 ;
     RECT  18.904 15.408 21.516 15.432 ;
     RECT  18.904 15.432 21.521 15.504 ;
     RECT  18.904 15.504 21.516 15.528 ;
     RECT  18.904 15.528 21.521 15.6 ;
     RECT  18.904 15.6 21.516 15.624 ;
     RECT  18.904 15.624 21.521 15.696 ;
     RECT  18.904 15.696 21.516 15.72 ;
     RECT  18.904 15.72 21.521 15.792 ;
     RECT  18.904 15.792 21.516 15.816 ;
     RECT  18.904 15.816 21.521 15.888 ;
     RECT  18.904 15.888 21.516 15.912 ;
     RECT  18.904 15.912 21.521 15.984 ;
     RECT  18.904 15.984 21.516 16.008 ;
     RECT  18.904 16.008 21.521 16.08 ;
     RECT  18.904 16.08 21.516 16.104 ;
     RECT  18.904 16.104 21.521 16.176 ;
     RECT  18.904 16.176 21.516 16.2 ;
     RECT  18.904 16.2 21.521 16.272 ;
     RECT  18.904 16.272 21.516 16.296 ;
     RECT  18.904 16.296 21.521 16.368 ;
     RECT  18.904 16.368 21.516 16.392 ;
     RECT  18.904 16.392 21.521 16.464 ;
     RECT  18.904 16.464 21.516 16.488 ;
     RECT  18.904 16.488 21.521 16.56 ;
     RECT  18.904 16.56 21.516 16.584 ;
     RECT  18.904 16.584 21.521 16.656 ;
     RECT  18.904 16.656 21.516 16.68 ;
     RECT  18.904 16.68 21.521 16.752 ;
     RECT  18.904 16.752 21.516 16.776 ;
     RECT  18.904 16.776 21.521 16.848 ;
     RECT  18.904 16.848 21.516 16.872 ;
     RECT  18.904 16.872 21.521 16.944 ;
     RECT  18.904 16.944 21.516 16.968 ;
     RECT  21.521 3.816 21.564 3.888 ;
     RECT  21.521 3.912 21.564 3.984 ;
     RECT  21.521 4.008 21.564 4.08 ;
     RECT  21.521 4.104 21.564 4.176 ;
     RECT  21.521 4.2 21.564 4.272 ;
     RECT  21.521 4.296 21.564 4.368 ;
     RECT  21.521 4.392 21.564 4.464 ;
     RECT  21.521 4.488 21.564 4.56 ;
     RECT  21.521 4.584 21.564 4.656 ;
     RECT  21.521 4.68 21.564 4.752 ;
     RECT  21.521 4.776 21.564 4.848 ;
     RECT  21.521 4.872 21.564 4.944 ;
     RECT  21.521 4.968 21.564 5.04 ;
     RECT  21.521 5.064 21.564 5.136 ;
     RECT  21.521 5.16 21.564 5.232 ;
     RECT  21.521 5.256 21.564 5.328 ;
     RECT  21.521 5.352 21.564 5.424 ;
     RECT  21.521 5.448 21.564 5.52 ;
     RECT  21.521 5.544 21.564 5.616 ;
     RECT  21.521 5.64 21.564 5.712 ;
     RECT  21.521 5.736 21.564 5.808 ;
     RECT  21.521 5.832 21.564 5.904 ;
     RECT  21.521 5.928 21.564 6 ;
     RECT  21.521 6.024 21.564 6.096 ;
     RECT  21.521 6.12 21.564 6.192 ;
     RECT  21.521 6.216 21.564 6.288 ;
     RECT  21.521 6.312 21.564 6.384 ;
     RECT  21.521 6.408 21.564 6.48 ;
     RECT  21.521 6.504 21.564 6.576 ;
     RECT  21.521 6.6 21.564 6.672 ;
     RECT  21.521 6.696 21.564 6.768 ;
     RECT  21.521 6.792 21.564 6.864 ;
     RECT  21.521 6.888 21.564 6.96 ;
     RECT  21.521 6.984 21.564 7.056 ;
     RECT  21.521 7.08 21.564 7.152 ;
     RECT  21.521 7.176 21.564 7.248 ;
     RECT  21.521 7.272 21.564 7.344 ;
     RECT  21.521 7.368 21.564 7.44 ;
     RECT  21.521 7.464 21.564 7.536 ;
     RECT  21.521 7.56 21.564 7.632 ;
     RECT  21.521 7.656 21.564 7.728 ;
     RECT  21.521 7.752 21.564 7.824 ;
     RECT  21.521 7.848 21.564 7.92 ;
     RECT  21.521 7.944 21.564 8.016 ;
     RECT  21.521 8.04 21.564 8.112 ;
     RECT  21.521 8.136 21.564 8.208 ;
     RECT  21.521 8.232 21.564 8.304 ;
     RECT  21.521 8.328 21.564 8.4 ;
     RECT  21.521 8.424 21.564 8.496 ;
     RECT  21.521 8.52 21.564 8.592 ;
     RECT  21.521 8.616 21.564 8.688 ;
     RECT  21.521 8.712 21.564 8.784 ;
     RECT  21.521 8.808 21.564 8.88 ;
     RECT  21.521 8.904 21.564 8.976 ;
     RECT  21.521 9 21.564 9.072 ;
     RECT  21.521 9.096 21.564 9.168 ;
     RECT  21.521 9.192 21.564 9.264 ;
     RECT  21.521 9.288 21.564 9.36 ;
     RECT  21.521 9.384 21.564 9.456 ;
     RECT  21.521 9.48 21.564 9.552 ;
     RECT  21.521 9.576 21.564 9.648 ;
     RECT  21.521 9.672 21.564 9.744 ;
     RECT  21.521 9.768 21.564 9.84 ;
     RECT  21.521 9.864 21.564 9.936 ;
     RECT  21.521 9.96 21.564 10.032 ;
     RECT  21.521 10.056 21.564 10.128 ;
     RECT  21.521 10.152 21.564 10.224 ;
     RECT  21.521 10.248 21.564 10.32 ;
     RECT  21.521 10.344 21.564 10.416 ;
     RECT  21.521 10.44 21.564 10.512 ;
     RECT  21.521 10.536 21.564 10.608 ;
     RECT  21.521 10.632 21.564 10.704 ;
     RECT  21.521 10.728 21.564 10.8 ;
     RECT  21.521 10.824 21.564 10.896 ;
     RECT  21.521 10.92 21.564 10.992 ;
     RECT  21.521 11.016 21.564 11.088 ;
     RECT  21.521 11.112 21.564 11.184 ;
     RECT  21.521 11.208 21.564 11.28 ;
     RECT  21.521 11.304 21.564 11.376 ;
     RECT  21.521 11.4 21.564 11.472 ;
     RECT  21.521 11.496 21.564 11.568 ;
     RECT  21.521 11.592 21.564 11.664 ;
     RECT  21.521 11.688 21.564 11.76 ;
     RECT  21.521 11.784 21.564 11.856 ;
     RECT  21.521 11.88 21.564 11.952 ;
     RECT  21.521 11.976 21.564 12.048 ;
     RECT  21.521 12.072 21.564 12.144 ;
     RECT  21.521 12.168 21.564 12.24 ;
     RECT  21.521 12.264 21.564 12.336 ;
     RECT  21.521 12.36 21.564 12.432 ;
     RECT  21.521 12.456 21.564 12.528 ;
     RECT  21.521 12.552 21.564 12.624 ;
     RECT  21.521 12.648 21.564 12.72 ;
     RECT  21.521 12.744 21.564 12.816 ;
     RECT  21.521 12.84 21.564 12.912 ;
     RECT  21.521 12.936 21.564 13.008 ;
     RECT  21.521 13.032 21.564 13.104 ;
     RECT  21.521 13.128 21.564 13.2 ;
     RECT  21.521 13.224 21.564 13.296 ;
     RECT  21.521 13.32 21.564 13.392 ;
     RECT  21.521 13.416 21.564 13.488 ;
     RECT  21.521 13.512 21.564 13.584 ;
     RECT  21.521 13.608 21.564 13.68 ;
     RECT  21.521 13.704 21.564 13.776 ;
     RECT  21.521 13.8 21.564 13.872 ;
     RECT  21.521 13.896 21.564 13.968 ;
     RECT  21.521 13.992 21.564 14.064 ;
     RECT  21.521 14.088 21.564 14.16 ;
     RECT  21.521 14.184 21.564 14.256 ;
     RECT  21.521 14.28 21.564 14.352 ;
     RECT  21.521 14.376 21.564 14.448 ;
     RECT  21.521 14.472 21.564 14.544 ;
     RECT  21.521 14.568 21.564 14.64 ;
     RECT  21.521 14.664 21.564 14.736 ;
     RECT  21.521 14.76 21.564 14.832 ;
     RECT  21.521 14.856 21.564 14.928 ;
     RECT  21.521 14.952 21.564 15.024 ;
     RECT  21.521 15.048 21.564 15.12 ;
     RECT  21.521 15.144 21.564 15.216 ;
     RECT  21.521 15.24 21.564 15.312 ;
     RECT  21.521 15.336 21.564 15.408 ;
     RECT  21.521 15.432 21.564 15.504 ;
     RECT  21.521 15.528 21.564 15.6 ;
     RECT  21.521 15.624 21.564 15.696 ;
     RECT  21.521 15.72 21.564 15.792 ;
     RECT  21.521 15.816 21.564 15.888 ;
     RECT  21.521 15.912 21.564 15.984 ;
     RECT  21.521 16.008 21.564 16.08 ;
     RECT  21.521 16.104 21.564 16.176 ;
     RECT  21.521 16.2 21.564 16.272 ;
     RECT  21.521 16.296 21.564 16.368 ;
     RECT  21.521 16.392 21.564 16.464 ;
     RECT  21.521 16.488 21.564 16.56 ;
     RECT  21.521 16.584 21.564 16.656 ;
     RECT  21.521 16.68 21.564 16.752 ;
     RECT  21.521 16.776 21.564 16.848 ;
     RECT  21.521 16.872 21.564 16.944 ;
    LAYER M5 ;
     RECT  7.848 0.016 7.92 0.084 ;
     RECT  7.824 0.084 7.944 0.085 ;
     RECT  2.4 2.137 2.52 2.151 ;
     RECT  5.1 2.137 5.22 2.151 ;
     RECT  7.632 0.085 7.944 2.151 ;
     RECT  10.5 2.137 10.62 2.151 ;
     RECT  13.2 2.137 13.32 2.151 ;
     RECT  15.9 2.137 16.02 2.151 ;
     RECT  18.6 2.137 18.72 2.151 ;
     RECT  7.632 2.151 8.112 2.581 ;
     RECT  5.1 2.151 5.412 2.821 ;
     RECT  4.992 2.821 6.312 3.539 ;
     RECT  2.4 2.151 2.712 3.733 ;
     RECT  7.632 2.581 8.952 3.875 ;
     RECT  0.144 4.309 0.168 4.499 ;
     RECT  5.1 3.539 5.412 4.501 ;
     RECT  7.632 3.875 8.112 4.501 ;
     RECT  4.512 4.501 5.412 4.645 ;
     RECT  4.176 4.645 5.412 5.077 ;
     RECT  6.864 4.501 8.112 5.077 ;
     RECT  15.9 2.151 16.212 5.125 ;
     RECT  4.176 5.077 8.112 5.171 ;
     RECT  2.4 3.733 2.808 5.219 ;
     RECT  4.512 5.171 5.976 6.035 ;
     RECT  15.9 5.125 16.488 6.419 ;
     RECT  7.344 5.171 8.112 6.563 ;
     RECT  5.1 6.035 5.976 6.899 ;
     RECT  0.144 7.141 0.168 7.331 ;
     RECT  7.632 6.563 8.112 7.765 ;
     RECT  5.1 6.899 5.736 8.341 ;
     RECT  0.144 8.773 0.168 8.963 ;
     RECT  7.632 7.765 8.28 9.539 ;
     RECT  14.832 9.301 14.856 9.587 ;
     RECT  5.1 8.341 5.784 9.781 ;
     RECT  7.632 9.539 8.232 10.067 ;
     RECT  7.632 10.067 8.112 10.453 ;
     RECT  4.896 9.781 5.784 10.645 ;
     RECT  14.832 10.885 14.856 11.267 ;
     RECT  0.144 10.597 0.168 11.363 ;
     RECT  14.832 12.613 14.856 12.755 ;
     RECT  4.896 10.645 6.264 12.853 ;
     RECT  2.4 5.219 2.712 12.997 ;
     RECT  7.44 10.453 8.112 12.997 ;
     RECT  4.512 12.853 6.264 13.045 ;
     RECT  7.44 12.997 8.232 13.045 ;
     RECT  2.4 12.997 2.808 13.477 ;
     RECT  4.512 13.045 8.232 13.763 ;
     RECT  4.512 13.763 8.112 14.197 ;
     RECT  2.4 13.477 2.856 14.677 ;
     RECT  0.144 13.333 0.168 14.819 ;
     RECT  4.08 14.197 8.112 14.915 ;
     RECT  4.08 14.915 5.64 15.011 ;
     RECT  6.768 14.915 8.112 15.299 ;
     RECT  9.408 15.013 9.432 15.299 ;
     RECT  10.5 2.151 10.812 15.349 ;
     RECT  21.408 15.781 21.432 15.971 ;
     RECT  2.4 14.677 2.904 16.019 ;
     RECT  4.08 15.011 5.592 16.019 ;
     RECT  4.176 16.019 5.592 16.309 ;
     RECT  4.176 16.309 5.688 17.267 ;
     RECT  7.44 15.299 8.112 17.267 ;
     RECT  4.176 17.267 5.544 17.699 ;
     RECT  9.648 15.349 10.812 18.035 ;
     RECT  4.176 17.699 5.412 18.131 ;
     RECT  2.4 16.019 2.712 19.449 ;
     RECT  5.1 18.131 5.412 19.449 ;
     RECT  7.8 17.267 8.112 19.449 ;
     RECT  10.5 18.035 10.812 19.449 ;
     RECT  13.2 2.151 13.512 19.449 ;
     RECT  15.9 6.419 16.212 19.449 ;
     RECT  18.6 2.151 18.912 19.449 ;
     RECT  2.4 19.449 2.52 19.463 ;
     RECT  5.1 19.449 5.22 19.463 ;
     RECT  7.8 19.449 7.92 19.463 ;
     RECT  10.5 19.449 10.62 19.463 ;
     RECT  13.2 19.449 13.32 19.463 ;
     RECT  15.9 19.449 16.02 19.463 ;
     RECT  18.6 19.449 18.72 19.463 ;
     RECT  6.312 2.821 7.632 3.539 ;
     RECT  4.992 3.539 5.1 4.501 ;
     RECT  5.412 3.539 7.632 4.501 ;
     RECT  5.412 4.501 6.864 5.077 ;
     RECT  2.808 4.645 4.176 5.171 ;
     RECT  5.976 5.171 7.344 6.563 ;
     RECT  5.736 6.899 5.784 8.341 ;
     RECT  13.512 9.301 14.832 9.587 ;
     RECT  14.856 9.301 15.9 9.587 ;
     RECT  13.512 9.587 15.9 10.885 ;
     RECT  6.264 10.645 7.44 13.045 ;
     RECT  13.512 10.885 14.832 11.267 ;
     RECT  14.856 10.885 15.9 11.267 ;
     RECT  13.512 11.267 15.9 12.613 ;
     RECT  13.512 12.613 14.832 12.755 ;
     RECT  14.856 12.613 15.9 12.755 ;
     RECT  8.112 13.763 8.232 15.013 ;
     RECT  2.856 14.197 4.08 14.677 ;
     RECT  2.904 14.677 4.08 16.019 ;
     RECT  5.64 14.915 6.768 15.011 ;
     RECT  5.592 15.011 6.768 15.299 ;
     RECT  8.112 15.013 9.408 15.299 ;
     RECT  9.432 15.013 10.5 15.299 ;
     RECT  5.592 15.299 5.688 16.309 ;
     RECT  9.648 15.299 10.5 15.349 ;
     RECT  2.712 16.019 4.176 18.131 ;
  END
END hbfd_rly_136_WE_rrfc
END LIBRARY
